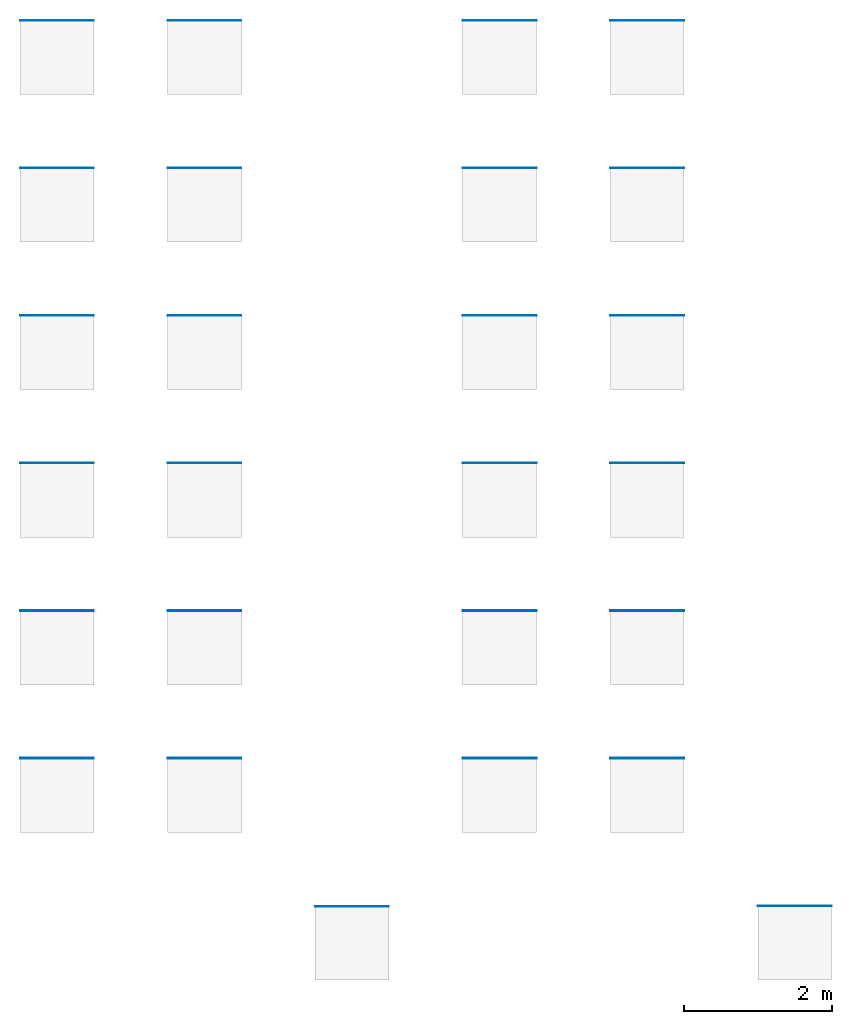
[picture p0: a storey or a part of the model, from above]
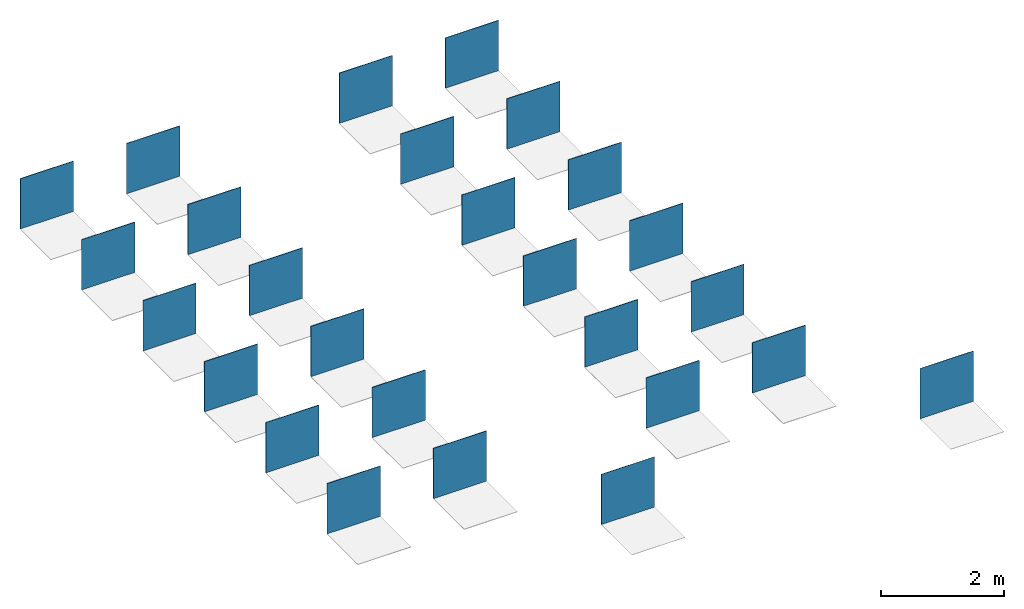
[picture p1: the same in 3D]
Properties of the parts of a building model (IFC2X3), part 1 of 4

# File
Description: ViewDefinition [CoordinationView_V2.0]
Time: 2025-06-20T15:38:36
Written by: The EXPRESS Data Manager Version 5.02.0100.07 : 28 Aug 2013
Made in: 21.1.90.15 - Exporter 21.1.90.15 - Alternate UI 21.1.90.15
Comment: STEP Physical File produced by: The EXPRESS Data Manager Version 5.02.0100.07 : 28 Aug 2013 * Module: EDMstepFileFactory/EDMstandAlone * Creation date: Fri Jun 20 15:38:36 2025 * Host: STB002 * Database: C:\Users\LARISS~1\AppData\Local\Temp\234e31d9-e186-458c-9206-d387dea7a233\cd15f4ba-808e-4852-9584-1646430fa52a\ifc * Database version: 5507 * Database creation date: Fri Jun 20 15:38:35 2025 * Schema: IFC2X3 * Model: DataRepository.ifc * Model creation date: Fri Jun 20 15:38:35 2025 * Header model: DataRepository.ifc_HeaderModel * Header model creation date: Fri Jun 20 15:38:35 2025 * EDMuser: sdai-user * EDMgroup: sdai-group * License ID and type: 5605 : Permanent license. Expiry date: * EDMstepFileFactory options: 020000

# IfcSite, Default
RefLatitude: 42, 24, 53, 508911; RefLongitude: -71, -15, -29, -58837; RefElevation: 0 mm
Pset_ProductRequirements - Category: Project Information

# IfcBuilding
Pset_BuildingCommon - NumberOfStoreys: 1
Pset_ProductRequirements - Category: Project Information

# IfcBuildingStorey: Level:Level 1, Level 1
LongName: Level 1; Elevation: 0 mm
Pset_AirSideSystemInformation - Name: Level 1
Pset_ProductRequirements - Name: Level 1; Category: Levels

# IfcCovering: Floor:REVIGRÉS-RULE-BASE-119,8x277,8-RECT-ALLOY, Floor:REVIGRÉS-RULE-BASE-119,8x277,8-RECT-ALLOY:18754
In: Level 1
Type - PredefinedType: FLOORING; Material: REVIGRÉS-RULE-BASE-119.8x277.8-RECT-ALLOY 6 mm
Type - Pset_CoveringCommon - Reference: 3021X4V711; Material: Grés porcelânico
Type - Pset_ElementShading - Roughness: 304.8 mm
Type - Pset_ManufacturerTypeInformation - Manufacturer: REVIGRÉS
Type - Pset_ProductRequirements - Category: Floors
Type - Pset_QuantityTakeOff - Reference: 3021X4V711
Type - IFC.REVIGRÉS-Dados do fabricante-Floor Covering - FabricanteURL: https://www.revigres.pt/; ReferenciaModelo: Rule; NumeroGlobalDeItemComercial: 3021X4V711; Acabamento: RECT; Material: Grés porcelânico; IdentificadorDoOperadorEconomico: 501840856; UrlFabricanteArtigo: https://www.revigres.pt/colecoes/omni; PaisOrigem: Portugal
Type - IFC.REVIGRÉS-Dados de desempenho-Floor Covering - LibertacaoDeCadmio: 0; LibertacaoDeChumbo: 0
Type - IFC.REVIGRÉS-Dados de especificação-Floor Covering - VariacaoTonalidade: 3; NivelDeTrafego: 5; EPavimento: Sim; ERevestimento: Sim; EExterno: Sim
Type - IFC.REVIGRÉS-Dados geométricos-Floor Covering - AlturaNominal: 6 mm; ComprimentoNominal: 119.8 mm; LarguraNominal: 277.8 mm
Type - IFC.REVIGRÉS-Dados de sustentabilidade-Floor Covering - ItemEParcialmenteReciclado: 0; EnergiaTermicaExportada: 0; ItemENovo: Sim; ItemEReciclado: Não; VidaÚtilEsperada: 50; SubstanciasPerigosas: Não; PotencialDeEsgotamentoAbioticoDosRecursosFosseis: 203; PotencialDeEsgotamentoAbioticoDosRecursosNaoFosseisMineraisEMetais: 0.000701; PotencialDeAquecimentoGlobalBiogenico: -0.48; CombustiveisFosseisComPotencialDeAquecimentoGlobal: 13.9; PotencialDeAquecimentoGlobalUsoDoSoloEMudancaDeUsoDoSolo: 0.0246; PotencialDeEutrofizacaoFraccaoDeNutrientesQueAtingemOCompartimentoFinalDeAguaDoce: 0.000189; PotencialDeEutrofizacaoFraccaoDeNutrientesQueAtingemOCompartimentoFinalMarinho: 0.0122; EnergiaRecuperada: 0.00739; ConsumoDeAguaDoce: 0.113; UtilizacaoLiquidaDeAguaDoce: 0.113; ResiduosPerigososEliminados: 0.00221; ResiduosNaoPerigososEliminados: 1.83; MassaTotalDeResiduosRadioactivosEliminados: 0.000394; EnergiaElectricaExportada: 1.55; MateriaisParaRecuperacaoDeEnergia: 0.00739; MateriaisParaReciclagem: 0.0253; UnidadeEPD: 1 m²
Type - IFC.REVIGRÉS-Dados gerais-Floor Covering - Nome: REVIGRÉS-RULE-BASE-119.8X277.8-RECT-ALLOY; TipoProduto: Prensado a seco: grupo BIa UGL | Grés porcelânico técnico; NumeroDeRegistoDAP: EPD-REV-20240006-CCC1-EN; ReferenciaDAP: -; UrlDOP: -
Classification: C3020 (Uniformat)
Pset_CoveringCommon - TotalThickness: 6 mm
IFC.REVIGRÉS-Dados do fabricante-Floor Covering - Type: Floor: REVIGRÉS-RULE-BASE-119,8x277,8-RECT-ALLOY
IFC.REVIGRÉS-Dados de desempenho-Floor Covering - Type: Floor: REVIGRÉS-RULE-BASE-119,8x277,8-RECT-ALLOY
IFC.REVIGRÉS-Dados de especificação-Floor Covering - Type: Floor: REVIGRÉS-RULE-BASE-119,8x277,8-RECT-ALLOY
IFC.REVIGRÉS-Dados geométricos-Floor Covering - Type: Floor: REVIGRÉS-RULE-BASE-119,8x277,8-RECT-ALLOY
IFC.REVIGRÉS-Dados de sustentabilidade-Floor Covering - Type: Floor: REVIGRÉS-RULE-BASE-119,8x277,8-RECT-ALLOY

# IfcCovering: Floor:REVIGRÉS-RULE-BASE-119,8x277,8-RECT-SMOG, Floor:REVIGRÉS-RULE-BASE-119,8x277,8-RECT-SMOG:17621
In: Level 1
Type - PredefinedType: FLOORING; Material: REVIGRÉS-RULE-BASE-119.8x277.8-RECT-SMOG 6 mm
Type - Pset_CoveringCommon - Reference: 3021X4V721; Material: Grés porcelânico
Type - Pset_ElementShading - Roughness: 304.8 mm
Type - Pset_ManufacturerTypeInformation - Manufacturer: REVIGRÉS
Type - Pset_ProductRequirements - Category: Floors
Type - Pset_QuantityTakeOff - Reference: 3021X4V721
Type - IFC.REVIGRÉS-Dados do fabricante-Floor Covering - FabricanteURL: https://www.revigres.pt/; ReferenciaModelo: Rule; NumeroGlobalDeItemComercial: 3021X4V721; Acabamento: RECT; Material: Grés porcelânico; IdentificadorDoOperadorEconomico: 501840856; UrlFabricanteArtigo: https://www.revigres.pt/colecoes/omni; PaisOrigem: Portugal
Type - IFC.REVIGRÉS-Dados de desempenho-Floor Covering - LibertacaoDeCadmio: 0; LibertacaoDeChumbo: 0
Type - IFC.REVIGRÉS-Dados de especificação-Floor Covering - VariacaoTonalidade: 3; NivelDeTrafego: 5; EPavimento: Sim; ERevestimento: Sim; EExterno: Sim
Type - IFC.REVIGRÉS-Dados geométricos-Floor Covering - AlturaNominal: 6 mm; ComprimentoNominal: 119.8 mm; LarguraNominal: 277.8 mm
Type - IFC.REVIGRÉS-Dados de sustentabilidade-Floor Covering - EnergiaTermicaExportada: 0; ItemENovo: Sim; ItemEParcialmenteReciclado: 0.23; ItemEReciclado: Sim; VidaÚtilEsperada: 50; SubstanciasPerigosas: Não; PotencialDeEsgotamentoAbioticoDosRecursosFosseis: 203; PotencialDeEsgotamentoAbioticoDosRecursosNaoFosseisMineraisEMetais: 0.000701; PotencialDeAquecimentoGlobalBiogenico: -0.48; CombustiveisFosseisComPotencialDeAquecimentoGlobal: 13.9; PotencialDeAquecimentoGlobalUsoDoSoloEMudancaDeUsoDoSolo: 0.0246; PotencialDeEutrofizacaoFraccaoDeNutrientesQueAtingemOCompartimentoFinalDeAguaDoce: 0.000189; PotencialDeEutrofizacaoFraccaoDeNutrientesQueAtingemOCompartimentoFinalMarinho: 0.0122; EnergiaRecuperada: 0.00739; ConsumoDeAguaDoce: 0.113; UtilizacaoLiquidaDeAguaDoce: 0.113; ResiduosPerigososEliminados: 0.00221; ResiduosNaoPerigososEliminados: 1.83; MassaTotalDeResiduosRadioactivosEliminados: 0.000394; EnergiaElectricaExportada: 1.55; MateriaisParaRecuperacaoDeEnergia: 0.00739; MateriaisParaReciclagem: 0.0253; UnidadeEPD: 1 m²
Type - IFC.REVIGRÉS-Dados gerais-Floor Covering - Nome: REVIGRÉS-RULE-BASE-119.8X277.8-RECT-SMOG; TipoProduto: Prensado a seco: grupo BIa UGL | Grés porcelânico técnico; NumeroDeRegistoDAP: EPD-REV-20240006-CCC1-EN; ReferenciaDAP: -; UrlDOP: -
Classification: C3020 (Uniformat)
Pset_CoveringCommon - TotalThickness: 6 mm
IFC.REVIGRÉS-Dados do fabricante-Floor Covering - Type: Floor: REVIGRÉS-RULE-BASE-119,8x277,8-RECT-SMOG
IFC.REVIGRÉS-Dados de desempenho-Floor Covering - Type: Floor: REVIGRÉS-RULE-BASE-119,8x277,8-RECT-SMOG
IFC.REVIGRÉS-Dados de especificação-Floor Covering - Type: Floor: REVIGRÉS-RULE-BASE-119,8x277,8-RECT-SMOG
IFC.REVIGRÉS-Dados geométricos-Floor Covering - Type: Floor: REVIGRÉS-RULE-BASE-119,8x277,8-RECT-SMOG
IFC.REVIGRÉS-Dados de sustentabilidade-Floor Covering - Type: Floor: REVIGRÉS-RULE-BASE-119,8x277,8-RECT-SMOG

# IfcCovering: Floor:REVIGRÉS-RULE-BASE-19,6x118,6-SILK-ALLOY, Floor:REVIGRÉS-RULE-BASE-19,6x118,6-SILK-ALLOY:2489
In: Level 1
Type - PredefinedType: FLOORING; Material: REVIGRÉS-RULE-BASE-19.6x118.6-SILK-ALLOY 10.5 mm
Type - Pset_CoveringCommon - Reference: 312GL8V711; Material: Grés porcelânico
Type - Pset_ElementShading - Roughness: 304.8 mm
Type - Pset_ManufacturerTypeInformation - Manufacturer: REVIGRÉS
Type - Pset_ProductRequirements - Category: Floors
Type - Pset_QuantityTakeOff - Reference: 312GL8V711
Type - IFC.REVIGRÉS-Dados do fabricante-Floor Covering - FabricanteURL: https://www.revigres.pt/; ReferenciaModelo: Rule; NumeroGlobalDeItemComercial: 312GL8V711; Acabamento: SILK; Material: Grés porcelânico; IdentificadorDoOperadorEconomico: 501840856; UrlFabricanteArtigo: https://www.revigres.pt/colecoes/rule; PaisOrigem: Portugal
Type - IFC.REVIGRÉS-Dados de desempenho-Floor Covering - Rectilinearidade: ± 0.2% máx.± 0.8 mm; Ortogonalidade: ± 0.2% máx.± 1.5 mm; PlanaridadeDaSuperficie: ± 0.3% máx. ± 1.8 mm; QualidadeDaSuperficie: Cumpre; AbsorcaoDeAgua: < 0.05%; ModuloDeRuptura: > 45 N/mm²; ResistenciaAFlexao: >3500 N; ResistenciaAAbrasaoProfunda: < 120 mm³; DilatacaoTermicaLinear: ≤ 8,0x10-6 °C-1; ResistenciaAoChoqueTermico: Resiste; DurabilidadeResistenciaAoGeloDegelo: Resiste; ResistenciaAoEscorregamentoDIN51130: R9; ResistenciaAoEscorregamentoDIN51097: A; ResistenciaAoEscorregamentoENV51097: A; ResistenciaAoEscorregamentoENV12633: Class 1; ResistenciaAoEscorregamentoANSIA1371: ≥0,42; ResistenciaAoDeslizamentoENV12633: Class 1; ResistenciaAsManchas: Class 5; ResistenciaABaixasConcentracoesDeAcidosEAlcalis: Classe LA; ResistenciaAAltasConcentracoesDeAcidosEAlcalis: Classe HA; LibertacaoDeCadmio: 0; LibertacaoDeChumbo: 0
Type - IFC.REVIGRÉS-Dados de especificação-Floor Covering - VariacaoTonalidade: 3; NivelDeTrafego: 5; EPavimento: Sim; ERevestimento: Sim; EExterno: Sim
Type - IFC.REVIGRÉS-Dados geométricos-Floor Covering - AlturaNominal: 10.5 mm; ComprimentoNominal: 19.6 mm; LarguraNominal: 118.6 mm
Type - IFC.REVIGRÉS-Dados de sustentabilidade-Floor Covering - ItemEParcialmenteReciclado: 0; EnergiaTermicaExportada: 0; ItemENovo: Sim; ItemEReciclado: Não; VidaÚtilEsperada: 50; SubstanciasPerigosas: Não; PotencialDeEsgotamentoAbioticoDosRecursosFosseis: 203; PotencialDeEsgotamentoAbioticoDosRecursosNaoFosseisMineraisEMetais: 0.000701; PotencialDeAquecimentoGlobalBiogenico: -0.48; CombustiveisFosseisComPotencialDeAquecimentoGlobal: 13.9; PotencialDeAquecimentoGlobalUsoDoSoloEMudancaDeUsoDoSolo: 0.0246; PotencialDeEutrofizacaoFraccaoDeNutrientesQueAtingemOCompartimentoFinalDeAguaDoce: 0.000189; PotencialDeEutrofizacaoFraccaoDeNutrientesQueAtingemOCompartimentoFinalMarinho: 0.0122; EnergiaRecuperada: 0.00739; ConsumoDeAguaDoce: 0.113; UtilizacaoLiquidaDeAguaDoce: 0.113; ResiduosPerigososEliminados: 0.00221; ResiduosNaoPerigososEliminados: 1.83; MassaTotalDeResiduosRadioactivosEliminados: 0.000394; EnergiaElectricaExportada: 1.55; MateriaisParaRecuperacaoDeEnergia: 0.00739; MateriaisParaReciclagem: 0.0253; UnidadeEPD: 1 m²
Type - IFC.REVIGRÉS-Dados gerais-Floor Covering - Nome: REVIGRÉS-RULE-BASE-19.6X118.6-SILK-ALLOY; TipoProduto: Prensado a seco: grupo BIa UGL | Grés porcelânico técnico; NumeroDeRegistoDAP: EPD-REV-20240006-CCC1-EN; ReferenciaDAP: -; UrlDOP: -
Classification: C3020 (Uniformat)
Pset_CoveringCommon - TotalThickness: 10.5 mm
IFC.REVIGRÉS-Dados do fabricante-Floor Covering - Type: Floor: REVIGRÉS-RULE-BASE-19,6x118,6-SILK-ALLOY
IFC.REVIGRÉS-Dados de desempenho-Floor Covering - Type: Floor: REVIGRÉS-RULE-BASE-19,6x118,6-SILK-ALLOY
IFC.REVIGRÉS-Dados de especificação-Floor Covering - Type: Floor: REVIGRÉS-RULE-BASE-19,6x118,6-SILK-ALLOY
IFC.REVIGRÉS-Dados geométricos-Floor Covering - Type: Floor: REVIGRÉS-RULE-BASE-19,6x118,6-SILK-ALLOY
IFC.REVIGRÉS-Dados de sustentabilidade-Floor Covering - Type: Floor: REVIGRÉS-RULE-BASE-19,6x118,6-SILK-ALLOY

# IfcCovering: Floor:REVIGRÉS-RULE-BASE-19,6x118,6-SILK-SMOG, Floor:REVIGRÉS-RULE-BASE-19,6x118,6-SILK-SMOG:10931
In: Level 1
Type - PredefinedType: FLOORING; Material: REVIGRÉS-RULE-BASE-19.6x118.6-SILK-SMOG 10.5 mm
Type - Pset_CoveringCommon - Reference: 312GL8V721; Material: Grés porcelânico
Type - Pset_ElementShading - Roughness: 304.8 mm
Type - Pset_ManufacturerTypeInformation - Manufacturer: REVIGRÉS
Type - Pset_ProductRequirements - Category: Floors
Type - Pset_QuantityTakeOff - Reference: 312GL8V721
Type - IFC.REVIGRÉS-Dados do fabricante-Floor Covering - FabricanteURL: https://www.revigres.pt/; ReferenciaModelo: Rule; NumeroGlobalDeItemComercial: 312GL8V721; Acabamento: SILK; Material: Grés porcelânico; IdentificadorDoOperadorEconomico: 501840856; UrlFabricanteArtigo: https://www.revigres.pt/colecoes/rule; PaisOrigem: Portugal
Type - IFC.REVIGRÉS-Dados de desempenho-Floor Covering - Rectilinearidade: ± 0.2% máx.± 0.8 mm; Ortogonalidade: ± 0.2% máx.± 1.5 mm; PlanaridadeDaSuperficie: ± 0.3% máx. ± 1.8 mm; QualidadeDaSuperficie: Cumpre; AbsorcaoDeAgua: < 0.05%; ModuloDeRuptura: > 45 N/mm²; ResistenciaAFlexao: >3500 N; ResistenciaAAbrasaoProfunda: < 120 mm³; DilatacaoTermicaLinear: ≤ 8,0x10-6 °C-1; ResistenciaAoChoqueTermico: Resiste; DurabilidadeResistenciaAoGeloDegelo: Resiste; ResistenciaAoEscorregamentoDIN51130: R9; ResistenciaAoEscorregamentoDIN51097: A; ResistenciaAoEscorregamentoENV51097: A; ResistenciaAoEscorregamentoENV12633: Class 1; ResistenciaAoEscorregamentoANSIA1371: ≥0,42; ResistenciaAoDeslizamentoENV12633: Class 1; ResistenciaAsManchas: Class 5; ResistenciaABaixasConcentracoesDeAcidosEAlcalis: Classe LA; ResistenciaAAltasConcentracoesDeAcidosEAlcalis: Classe HA; LibertacaoDeCadmio: 0; LibertacaoDeChumbo: 0
Type - IFC.REVIGRÉS-Dados de especificação-Floor Covering - VariacaoTonalidade: 3; NivelDeTrafego: 5; EPavimento: Sim; ERevestimento: Sim; EExterno: Sim
Type - IFC.REVIGRÉS-Dados geométricos-Floor Covering - AlturaNominal: 10.5 mm; ComprimentoNominal: 19.6 mm; LarguraNominal: 118.6 mm
Type - IFC.REVIGRÉS-Dados de sustentabilidade-Floor Covering - EnergiaTermicaExportada: 0; ItemENovo: Sim; ItemEParcialmenteReciclado: 0.23; ItemEReciclado: Sim; VidaÚtilEsperada: 50; SubstanciasPerigosas: Não; PotencialDeEsgotamentoAbioticoDosRecursosFosseis: 203; PotencialDeEsgotamentoAbioticoDosRecursosNaoFosseisMineraisEMetais: 0.000701; PotencialDeAquecimentoGlobalBiogenico: -0.48; CombustiveisFosseisComPotencialDeAquecimentoGlobal: 13.9; PotencialDeAquecimentoGlobalUsoDoSoloEMudancaDeUsoDoSolo: 0.0246; PotencialDeEutrofizacaoFraccaoDeNutrientesQueAtingemOCompartimentoFinalDeAguaDoce: 0.000189; PotencialDeEutrofizacaoFraccaoDeNutrientesQueAtingemOCompartimentoFinalMarinho: 0.0122; EnergiaRecuperada: 0.00739; ConsumoDeAguaDoce: 0.113; UtilizacaoLiquidaDeAguaDoce: 0.113; ResiduosPerigososEliminados: 0.00221; ResiduosNaoPerigososEliminados: 1.83; MassaTotalDeResiduosRadioactivosEliminados: 0.000394; EnergiaElectricaExportada: 1.55; MateriaisParaRecuperacaoDeEnergia: 0.00739; MateriaisParaReciclagem: 0.0253; UnidadeEPD: 1 m²
Type - IFC.REVIGRÉS-Dados gerais-Floor Covering - Nome: REVIGRÉS-RULE-BASE-19.6X118.6-SILK-SMOG; TipoProduto: Prensado a seco: grupo BIa UGL | Grés porcelânico técnico; NumeroDeRegistoDAP: EPD-REV-20240006-CCC1-EN; ReferenciaDAP: -; UrlDOP: -
Classification: C3020 (Uniformat)
Pset_CoveringCommon - TotalThickness: 10.5 mm
IFC.REVIGRÉS-Dados do fabricante-Floor Covering - Type: Floor: REVIGRÉS-RULE-BASE-19,6x118,6-SILK-SMOG
IFC.REVIGRÉS-Dados de desempenho-Floor Covering - Type: Floor: REVIGRÉS-RULE-BASE-19,6x118,6-SILK-SMOG
IFC.REVIGRÉS-Dados de especificação-Floor Covering - Type: Floor: REVIGRÉS-RULE-BASE-19,6x118,6-SILK-SMOG
IFC.REVIGRÉS-Dados geométricos-Floor Covering - Type: Floor: REVIGRÉS-RULE-BASE-19,6x118,6-SILK-SMOG
IFC.REVIGRÉS-Dados de sustentabilidade-Floor Covering - Type: Floor: REVIGRÉS-RULE-BASE-19,6x118,6-SILK-SMOG

# IfcCovering: Floor:REVIGRÉS-RULE-BASE-19,6x118,6-SOFT GRIP-ALLOY, Floor:REVIGRÉS-RULE-BASE-19,6x118,6-SOFT GRIP-ALLOY:11150
In: Level 1
Type - PredefinedType: FLOORING; Material: REVIGRÉS-RULE-BASE-19.6x118.6-SOFT GRIP-ALLOY 10.5 mm
Type - Pset_CoveringCommon - Reference: 3121L8V711; Material: Grés porcelânico
Type - Pset_ElementShading - Roughness: 304.8 mm
Type - Pset_ManufacturerTypeInformation - Manufacturer: REVIGRÉS
Type - Pset_ProductRequirements - Category: Floors
Type - Pset_QuantityTakeOff - Reference: 3121L8V711
Type - IFC.REVIGRÉS-Dados do fabricante-Floor Covering - FabricanteURL: https://www.revigres.pt/; ReferenciaModelo: Rule; NumeroGlobalDeItemComercial: 3121L8V711; Acabamento: SOFT GRIP; Material: Grés porcelânico; IdentificadorDoOperadorEconomico: 501840856; UrlFabricanteArtigo: https://www.revigres.pt/colecoes/rule; PaisOrigem: Portugal
Type - IFC.REVIGRÉS-Dados de desempenho-Floor Covering - Rectilinearidade: ± 0.2% máx.± 0.8 mm; Ortogonalidade: ± 0.2% máx.± 1.5 mm; PlanaridadeDaSuperficie: ± 0.3% máx. ± 1.8 mm; QualidadeDaSuperficie: Cumpre; AbsorcaoDeAgua: < 0.05%; ModuloDeRuptura: > 45 N/mm²; ResistenciaAFlexao: >3500 N; ResistenciaAAbrasaoProfunda: < 120 mm³; DilatacaoTermicaLinear: ≤ 8,0x10-6 °C-1; ResistenciaAoChoqueTermico: Resiste; DurabilidadeResistenciaAoGeloDegelo: Resiste; ResistenciaAoEscorregamentoDIN51130: R11; ResistenciaAoEscorregamentoDIN51097: B; ResistenciaAoEscorregamentoENV51097: B; ResistenciaAoEscorregamentoENV12633: Class 2; ResistenciaAoEscorregamentoBS7976: >36; ResistenciaAoEscorregamentoANSIA1371: ≥0,42; ResistenciaAoDeslizamentoENV12633: Class 2; ResistenciaAoDeslizamentoBS7976: >36; ResistenciaAsManchas: Class 5; ResistenciaABaixasConcentracoesDeAcidosEAlcalis: Classe LA; ResistenciaAAltasConcentracoesDeAcidosEAlcalis: Classe HA; LibertacaoDeCadmio: 0; LibertacaoDeChumbo: 0
Type - IFC.REVIGRÉS-Dados de especificação-Floor Covering - VariacaoTonalidade: 3; NivelDeTrafego: 5; EPavimento: Sim; ERevestimento: Sim; EExterno: Sim
Type - IFC.REVIGRÉS-Dados geométricos-Floor Covering - AlturaNominal: 10.5 mm; ComprimentoNominal: 19.6 mm; LarguraNominal: 118.6 mm
Type - IFC.REVIGRÉS-Dados de sustentabilidade-Floor Covering - ItemEParcialmenteReciclado: 0; EnergiaTermicaExportada: 0; ItemENovo: Sim; ItemEReciclado: Não; VidaÚtilEsperada: 50; SubstanciasPerigosas: Não; PotencialDeEsgotamentoAbioticoDosRecursosFosseis: 203; PotencialDeEsgotamentoAbioticoDosRecursosNaoFosseisMineraisEMetais: 0.000701; PotencialDeAquecimentoGlobalBiogenico: -0.48; CombustiveisFosseisComPotencialDeAquecimentoGlobal: 13.9; PotencialDeAquecimentoGlobalUsoDoSoloEMudancaDeUsoDoSolo: 0.0246; PotencialDeEutrofizacaoFraccaoDeNutrientesQueAtingemOCompartimentoFinalDeAguaDoce: 0.000189; PotencialDeEutrofizacaoFraccaoDeNutrientesQueAtingemOCompartimentoFinalMarinho: 0.0122; EnergiaRecuperada: 0.00739; ConsumoDeAguaDoce: 0.113; UtilizacaoLiquidaDeAguaDoce: 0.113; ResiduosPerigososEliminados: 0.00221; ResiduosNaoPerigososEliminados: 1.83; MassaTotalDeResiduosRadioactivosEliminados: 0.000394; EnergiaElectricaExportada: 1.55; MateriaisParaRecuperacaoDeEnergia: 0.00739; MateriaisParaReciclagem: 0.0253; UnidadeEPD: 1 m²
Type - IFC.REVIGRÉS-Dados gerais-Floor Covering - Nome: REVIGRÉS-RULE-BASE-19.6X118.6-SOFT GRIP-ALLOY; TipoProduto: Prensado a seco: grupo BIa UGL | Grés porcelânico técnico; NumeroDeRegistoDAP: EPD-REV-20240006-CCC1-EN; ReferenciaDAP: -; UrlDOP: -
Classification: C3020 (Uniformat)
Pset_CoveringCommon - TotalThickness: 10.5 mm
IFC.REVIGRÉS-Dados do fabricante-Floor Covering - Type: Floor: REVIGRÉS-RULE-BASE-19,6x118,6-SOFT GRIP-ALLOY
IFC.REVIGRÉS-Dados de desempenho-Floor Covering - Type: Floor: REVIGRÉS-RULE-BASE-19,6x118,6-SOFT GRIP-ALLOY
IFC.REVIGRÉS-Dados de especificação-Floor Covering - Type: Floor: REVIGRÉS-RULE-BASE-19,6x118,6-SOFT GRIP-ALLOY
IFC.REVIGRÉS-Dados geométricos-Floor Covering - Type: Floor: REVIGRÉS-RULE-BASE-19,6x118,6-SOFT GRIP-ALLOY
IFC.REVIGRÉS-Dados de sustentabilidade-Floor Covering - Type: Floor: REVIGRÉS-RULE-BASE-19,6x118,6-SOFT GRIP-ALLOY

# IfcCovering: Floor:REVIGRÉS-RULE-BASE-19,6x118,6-SOFT GRIP-SMOG, Floor:REVIGRÉS-RULE-BASE-19,6x118,6-SOFT GRIP-SMOG:11228
In: Level 1
Type - PredefinedType: FLOORING; Material: REVIGRÉS-RULE-BASE-19.6x118.6-SOFT GRIP-SMOG 10.5 mm
Type - Pset_CoveringCommon - Reference: 312FL8V721; Material: Grés porcelânico
Type - Pset_ElementShading - Roughness: 304.8 mm
Type - Pset_ManufacturerTypeInformation - Manufacturer: REVIGRÉS
Type - Pset_ProductRequirements - Category: Floors
Type - Pset_QuantityTakeOff - Reference: 312FL8V721
Type - IFC.REVIGRÉS-Dados do fabricante-Floor Covering - FabricanteURL: https://www.revigres.pt/; ReferenciaModelo: Rule; NumeroGlobalDeItemComercial: 312FL8V721; Acabamento: SOFT GRIP; Material: Grés porcelânico; IdentificadorDoOperadorEconomico: 501840856; UrlFabricanteArtigo: https://www.revigres.pt/colecoes/rule; PaisOrigem: Portugal
Type - IFC.REVIGRÉS-Dados de desempenho-Floor Covering - Rectilinearidade: ± 0.2% máx.± 0.8 mm; Ortogonalidade: ± 0.2% máx.± 1.5 mm; PlanaridadeDaSuperficie: ± 0.3% máx. ± 1.8 mm; QualidadeDaSuperficie: Cumpre; AbsorcaoDeAgua: < 0.05%; ModuloDeRuptura: > 45 N/mm²; ResistenciaAFlexao: >3500 N; ResistenciaAAbrasaoProfunda: < 120 mm³; DilatacaoTermicaLinear: ≤ 8,0x10-6 °C-1; ResistenciaAoChoqueTermico: Resiste; DurabilidadeResistenciaAoGeloDegelo: Resiste; ResistenciaAoEscorregamentoDIN51130: R11; ResistenciaAoEscorregamentoDIN51097: B; ResistenciaAoEscorregamentoENV51097: B; ResistenciaAoEscorregamentoENV12633: Class 2; ResistenciaAoEscorregamentoBS7976: >36; ResistenciaAoEscorregamentoANSIA1371: ≥0,42; ResistenciaAoDeslizamentoENV12633: Class 2; ResistenciaAoDeslizamentoBS7976: >36; ResistenciaAsManchas: Class 5; ResistenciaABaixasConcentracoesDeAcidosEAlcalis: Classe LA; ResistenciaAAltasConcentracoesDeAcidosEAlcalis: Classe HA; LibertacaoDeCadmio: 0; LibertacaoDeChumbo: 0
Type - IFC.REVIGRÉS-Dados de especificação-Floor Covering - VariacaoTonalidade: 3; NivelDeTrafego: 5; EPavimento: Sim; ERevestimento: Sim; EExterno: Sim
Type - IFC.REVIGRÉS-Dados geométricos-Floor Covering - AlturaNominal: 10.5 mm; ComprimentoNominal: 19.6 mm; LarguraNominal: 118.6 mm
Type - IFC.REVIGRÉS-Dados de sustentabilidade-Floor Covering - EnergiaTermicaExportada: 0; ItemENovo: Sim; ItemEParcialmenteReciclado: 0.23; ItemEReciclado: Sim; VidaÚtilEsperada: 50; SubstanciasPerigosas: Não; PotencialDeEsgotamentoAbioticoDosRecursosFosseis: 203; PotencialDeEsgotamentoAbioticoDosRecursosNaoFosseisMineraisEMetais: 0.000701; PotencialDeAquecimentoGlobalBiogenico: -0.48; CombustiveisFosseisComPotencialDeAquecimentoGlobal: 13.9; PotencialDeAquecimentoGlobalUsoDoSoloEMudancaDeUsoDoSolo: 0.0246; PotencialDeEutrofizacaoFraccaoDeNutrientesQueAtingemOCompartimentoFinalDeAguaDoce: 0.000189; PotencialDeEutrofizacaoFraccaoDeNutrientesQueAtingemOCompartimentoFinalMarinho: 0.0122; EnergiaRecuperada: 0.00739; ConsumoDeAguaDoce: 0.113; UtilizacaoLiquidaDeAguaDoce: 0.113; ResiduosPerigososEliminados: 0.00221; ResiduosNaoPerigososEliminados: 1.83; MassaTotalDeResiduosRadioactivosEliminados: 0.000394; EnergiaElectricaExportada: 1.55; MateriaisParaRecuperacaoDeEnergia: 0.00739; MateriaisParaReciclagem: 0.0253; UnidadeEPD: 1 m²
Type - IFC.REVIGRÉS-Dados gerais-Floor Covering - Nome: REVIGRÉS-RULE-BASE-19.6X118.6-SOFT GRIP-SMOG; TipoProduto: Prensado a seco: grupo BIa UGL | Grés porcelânico técnico; NumeroDeRegistoDAP: EPD-REV-20240006-CCC1-EN; ReferenciaDAP: -; UrlDOP: -
Classification: C3020 (Uniformat)
Pset_CoveringCommon - TotalThickness: 10.5 mm
IFC.REVIGRÉS-Dados do fabricante-Floor Covering - Type: Floor: REVIGRÉS-RULE-BASE-19,6x118,6-SOFT GRIP-SMOG
IFC.REVIGRÉS-Dados de desempenho-Floor Covering - Type: Floor: REVIGRÉS-RULE-BASE-19,6x118,6-SOFT GRIP-SMOG
IFC.REVIGRÉS-Dados de especificação-Floor Covering - Type: Floor: REVIGRÉS-RULE-BASE-19,6x118,6-SOFT GRIP-SMOG
IFC.REVIGRÉS-Dados geométricos-Floor Covering - Type: Floor: REVIGRÉS-RULE-BASE-19,6x118,6-SOFT GRIP-SMOG
IFC.REVIGRÉS-Dados de sustentabilidade-Floor Covering - Type: Floor: REVIGRÉS-RULE-BASE-19,6x118,6-SOFT GRIP-SMOG

# IfcCovering: Floor:REVIGRÉS-RULE-BASE-19,6x178-SILK-ALLOY, Floor:REVIGRÉS-RULE-BASE-19,6x178-SILK-ALLOY:11306
In: Level 1
Type - PredefinedType: FLOORING; Material: REVIGRÉS-RULE-BASE-19.6x178-SILK-ALLOY 11.2 mm
Type - Pset_CoveringCommon - Reference: 312GS8V711; Material: Grés porcelânico
Type - Pset_ElementShading - Roughness: 304.8 mm
Type - Pset_ManufacturerTypeInformation - Manufacturer: REVIGRÉS
Type - Pset_ProductRequirements - Category: Floors
Type - Pset_QuantityTakeOff - Reference: 312GS8V711
Type - IFC.REVIGRÉS-Dados do fabricante-Floor Covering - FabricanteURL: https://www.revigres.pt/; ReferenciaModelo: Rule; NumeroGlobalDeItemComercial: 312GS8V711; Acabamento: SILK; Material: Grés porcelânico; IdentificadorDoOperadorEconomico: 501840856; UrlFabricanteArtigo: https://www.revigres.pt/colecoes/rule; PaisOrigem: Portugal
Type - IFC.REVIGRÉS-Dados de desempenho-Floor Covering - Rectilinearidade: ± 0.2% máx.± 0.8 mm; Ortogonalidade: ± 0.2% máx.± 1.5 mm; PlanaridadeDaSuperficie: ± 0.3% máx. ± 1.8 mm; QualidadeDaSuperficie: Cumpre; AbsorcaoDeAgua: < 0.05%; ModuloDeRuptura: > 45 N/mm²; ResistenciaAFlexao: >3500 N; ResistenciaAAbrasaoProfunda: < 120 mm³; DilatacaoTermicaLinear: ≤ 8,0x10-6 °C-1; ResistenciaAoChoqueTermico: Resiste; DurabilidadeResistenciaAoGeloDegelo: Resiste; ResistenciaAoEscorregamentoDIN51130: R9; ResistenciaAoEscorregamentoDIN51097: A; ResistenciaAoEscorregamentoENV51097: A; ResistenciaAoEscorregamentoENV12633: Class 1; ResistenciaAoEscorregamentoANSIA1371: ≥0,42; ResistenciaAoDeslizamentoENV12633: Class 1; ResistenciaAsManchas: Class 5; ResistenciaABaixasConcentracoesDeAcidosEAlcalis: Classe LA; ResistenciaAAltasConcentracoesDeAcidosEAlcalis: Classe HA; LibertacaoDeCadmio: 0; LibertacaoDeChumbo: 0
Type - IFC.REVIGRÉS-Dados de especificação-Floor Covering - VariacaoTonalidade: 3; NivelDeTrafego: 5; EPavimento: Sim; ERevestimento: Sim; EExterno: Sim
Type - IFC.REVIGRÉS-Dados geométricos-Floor Covering - AlturaNominal: 11.2 mm; ComprimentoNominal: 19.6 mm; LarguraNominal: 178 mm
Type - IFC.REVIGRÉS-Dados de sustentabilidade-Floor Covering - ItemEParcialmenteReciclado: 0; EnergiaTermicaExportada: 0; ItemENovo: Sim; ItemEReciclado: Não; VidaÚtilEsperada: 50; SubstanciasPerigosas: Não; PotencialDeEsgotamentoAbioticoDosRecursosFosseis: 203; PotencialDeEsgotamentoAbioticoDosRecursosNaoFosseisMineraisEMetais: 0.000701; PotencialDeAquecimentoGlobalBiogenico: -0.48; CombustiveisFosseisComPotencialDeAquecimentoGlobal: 13.9; PotencialDeAquecimentoGlobalUsoDoSoloEMudancaDeUsoDoSolo: 0.0246; PotencialDeEutrofizacaoFraccaoDeNutrientesQueAtingemOCompartimentoFinalDeAguaDoce: 0.000189; PotencialDeEutrofizacaoFraccaoDeNutrientesQueAtingemOCompartimentoFinalMarinho: 0.0122; EnergiaRecuperada: 0.00739; ConsumoDeAguaDoce: 0.113; UtilizacaoLiquidaDeAguaDoce: 0.113; ResiduosPerigososEliminados: 0.00221; ResiduosNaoPerigososEliminados: 1.83; MassaTotalDeResiduosRadioactivosEliminados: 0.000394; EnergiaElectricaExportada: 1.55; MateriaisParaRecuperacaoDeEnergia: 0.00739; MateriaisParaReciclagem: 0.0253; UnidadeEPD: 1 m²
Type - IFC.REVIGRÉS-Dados gerais-Floor Covering - Nome: REVIGRÉS-RULE-BASE-19.6X178-SILK-ALLOY; TipoProduto: Prensado a seco: grupo BIa UGL | Grés porcelânico técnico; NumeroDeRegistoDAP: EPD-REV-20240006-CCC1-EN; ReferenciaDAP: -; UrlDOP: -
Classification: C3020 (Uniformat)
Pset_CoveringCommon - TotalThickness: 11.2 mm
IFC.REVIGRÉS-Dados do fabricante-Floor Covering - Type: Floor: REVIGRÉS-RULE-BASE-19,6x178-SILK-ALLOY
IFC.REVIGRÉS-Dados de desempenho-Floor Covering - Type: Floor: REVIGRÉS-RULE-BASE-19,6x178-SILK-ALLOY
IFC.REVIGRÉS-Dados de especificação-Floor Covering - Type: Floor: REVIGRÉS-RULE-BASE-19,6x178-SILK-ALLOY
IFC.REVIGRÉS-Dados geométricos-Floor Covering - Type: Floor: REVIGRÉS-RULE-BASE-19,6x178-SILK-ALLOY
IFC.REVIGRÉS-Dados de sustentabilidade-Floor Covering - Type: Floor: REVIGRÉS-RULE-BASE-19,6x178-SILK-ALLOY

# IfcCovering: Floor:REVIGRÉS-RULE-BASE-19,6x178-SILK-SMOG, Floor:REVIGRÉS-RULE-BASE-19,6x178-SILK-SMOG:11369
In: Level 1
Type - PredefinedType: FLOORING; Material: REVIGRÉS-RULE-BASE-19.6x178-SILK-SMOG 11.2 mm
Type - Pset_CoveringCommon - Reference: 312GS8V721; Material: Grés porcelânico
Type - Pset_ElementShading - Roughness: 304.8 mm
Type - Pset_ManufacturerTypeInformation - Manufacturer: REVIGRÉS
Type - Pset_ProductRequirements - Category: Floors
Type - Pset_QuantityTakeOff - Reference: 312GS8V721
Type - IFC.REVIGRÉS-Dados do fabricante-Floor Covering - FabricanteURL: https://www.revigres.pt/; ReferenciaModelo: Rule; NumeroGlobalDeItemComercial: 312GS8V721; Acabamento: SILK; Material: Grés porcelânico; IdentificadorDoOperadorEconomico: 501840856; UrlFabricanteArtigo: https://www.revigres.pt/colecoes/rule; PaisOrigem: Portugal
Type - IFC.REVIGRÉS-Dados de desempenho-Floor Covering - Rectilinearidade: ± 0.2% máx.± 0.8 mm; Ortogonalidade: ± 0.2% máx.± 1.5 mm; PlanaridadeDaSuperficie: ± 0.3% máx. ± 1.8 mm; QualidadeDaSuperficie: Cumpre; AbsorcaoDeAgua: < 0.05%; ModuloDeRuptura: > 45 N/mm²; ResistenciaAFlexao: >3500 N; ResistenciaAAbrasaoProfunda: < 120 mm³; DilatacaoTermicaLinear: ≤ 8,0x10-6 °C-1; ResistenciaAoChoqueTermico: Resiste; DurabilidadeResistenciaAoGeloDegelo: Resiste; ResistenciaAoEscorregamentoDIN51130: R9; ResistenciaAoEscorregamentoDIN51097: A; ResistenciaAoEscorregamentoENV51097: A; ResistenciaAoEscorregamentoENV12633: Class 1; ResistenciaAoEscorregamentoANSIA1371: ≥0,42; ResistenciaAoDeslizamentoENV12633: Class 1; ResistenciaAsManchas: Class 5; ResistenciaABaixasConcentracoesDeAcidosEAlcalis: Classe LA; ResistenciaAAltasConcentracoesDeAcidosEAlcalis: Classe HA; LibertacaoDeCadmio: 0; LibertacaoDeChumbo: 0
Type - IFC.REVIGRÉS-Dados de especificação-Floor Covering - VariacaoTonalidade: 3; NivelDeTrafego: 5; EPavimento: Sim; ERevestimento: Sim; EExterno: Sim
Type - IFC.REVIGRÉS-Dados geométricos-Floor Covering - AlturaNominal: 11.2 mm; ComprimentoNominal: 19.6 mm; LarguraNominal: 178 mm
Type - IFC.REVIGRÉS-Dados de sustentabilidade-Floor Covering - EnergiaTermicaExportada: 0; ItemENovo: Sim; ItemEParcialmenteReciclado: 0.23; ItemEReciclado: Sim; VidaÚtilEsperada: 50; SubstanciasPerigosas: Não; PotencialDeEsgotamentoAbioticoDosRecursosFosseis: 203; PotencialDeEsgotamentoAbioticoDosRecursosNaoFosseisMineraisEMetais: 0.000701; PotencialDeAquecimentoGlobalBiogenico: -0.48; CombustiveisFosseisComPotencialDeAquecimentoGlobal: 13.9; PotencialDeAquecimentoGlobalUsoDoSoloEMudancaDeUsoDoSolo: 0.0246; PotencialDeEutrofizacaoFraccaoDeNutrientesQueAtingemOCompartimentoFinalDeAguaDoce: 0.000189; PotencialDeEutrofizacaoFraccaoDeNutrientesQueAtingemOCompartimentoFinalMarinho: 0.0122; EnergiaRecuperada: 0.00739; ConsumoDeAguaDoce: 0.113; UtilizacaoLiquidaDeAguaDoce: 0.113; ResiduosPerigososEliminados: 0.00221; ResiduosNaoPerigososEliminados: 1.83; MassaTotalDeResiduosRadioactivosEliminados: 0.000394; EnergiaElectricaExportada: 1.55; MateriaisParaRecuperacaoDeEnergia: 0.00739; MateriaisParaReciclagem: 0.0253; UnidadeEPD: 1 m²
Type - IFC.REVIGRÉS-Dados gerais-Floor Covering - Nome: REVIGRÉS-RULE-BASE-19.6X178-SILK-SMOG; TipoProduto: Prensado a seco: grupo BIa UGL | Grés porcelânico técnico; NumeroDeRegistoDAP: EPD-REV-20240006-CCC1-EN; ReferenciaDAP: -; UrlDOP: -
Classification: C3020 (Uniformat)
Pset_CoveringCommon - TotalThickness: 11.2 mm
IFC.REVIGRÉS-Dados do fabricante-Floor Covering - Type: Floor: REVIGRÉS-RULE-BASE-19,6x178-SILK-SMOG
IFC.REVIGRÉS-Dados de desempenho-Floor Covering - Type: Floor: REVIGRÉS-RULE-BASE-19,6x178-SILK-SMOG
IFC.REVIGRÉS-Dados de especificação-Floor Covering - Type: Floor: REVIGRÉS-RULE-BASE-19,6x178-SILK-SMOG
IFC.REVIGRÉS-Dados geométricos-Floor Covering - Type: Floor: REVIGRÉS-RULE-BASE-19,6x178-SILK-SMOG
IFC.REVIGRÉS-Dados de sustentabilidade-Floor Covering - Type: Floor: REVIGRÉS-RULE-BASE-19,6x178-SILK-SMOG

# IfcCovering: Floor:REVIGRÉS-RULE-BASE-19,6x178-SOFT GRIP-ALLOY, Floor:REVIGRÉS-RULE-BASE-19,6x178-SOFT GRIP-ALLOY:11431
In: Level 1
Type - PredefinedType: FLOORING; Material: REVIGRÉS-RULE-BASE-19.6x178-SOFT GRIP-ALLOY 11.2 mm
Type - Pset_CoveringCommon - Reference: 312FS8V711; Material: Grés porcelânico
Type - Pset_ElementShading - Roughness: 304.8 mm
Type - Pset_ManufacturerTypeInformation - Manufacturer: REVIGRÉS
Type - Pset_ProductRequirements - Category: Floors
Type - Pset_QuantityTakeOff - Reference: 312FS8V711
Type - IFC.REVIGRÉS-Dados do fabricante-Floor Covering - FabricanteURL: https://www.revigres.pt/; ReferenciaModelo: Rule; NumeroGlobalDeItemComercial: 312FS8V711; Acabamento: SOFT GRIP; Material: Grés porcelânico; IdentificadorDoOperadorEconomico: 501840856; UrlFabricanteArtigo: https://www.revigres.pt/colecoes/rule; PaisOrigem: Portugal
Type - IFC.REVIGRÉS-Dados de desempenho-Floor Covering - Rectilinearidade: ± 0.2% máx.± 0.8 mm; Ortogonalidade: ± 0.2% máx.± 1.5 mm; PlanaridadeDaSuperficie: ± 0.3% máx. ± 1.8 mm; QualidadeDaSuperficie: Cumpre; AbsorcaoDeAgua: < 0.05%; ModuloDeRuptura: > 45 N/mm²; ResistenciaAFlexao: >3500 N; ResistenciaAAbrasaoProfunda: < 120 mm³; DilatacaoTermicaLinear: ≤ 8,0x10-6 °C-1; ResistenciaAoChoqueTermico: Resiste; DurabilidadeResistenciaAoGeloDegelo: Resiste; ResistenciaAoEscorregamentoDIN51130: R11; ResistenciaAoEscorregamentoDIN51097: B; ResistenciaAoEscorregamentoENV51097: B; ResistenciaAoEscorregamentoENV12633: Class 2; ResistenciaAoEscorregamentoBS7976: >36; ResistenciaAoEscorregamentoANSIA1371: ≥0,42; ResistenciaAoDeslizamentoENV12633: Class 2; ResistenciaAoDeslizamentoBS7976: >36; ResistenciaAsManchas: Class 5; ResistenciaABaixasConcentracoesDeAcidosEAlcalis: Classe LA; ResistenciaAAltasConcentracoesDeAcidosEAlcalis: Classe HA; LibertacaoDeCadmio: 0; LibertacaoDeChumbo: 0
Type - IFC.REVIGRÉS-Dados de especificação-Floor Covering - VariacaoTonalidade: 3; NivelDeTrafego: 5; EPavimento: Sim; ERevestimento: Sim; EExterno: Sim
Type - IFC.REVIGRÉS-Dados geométricos-Floor Covering - AlturaNominal: 11.2 mm; ComprimentoNominal: 19.6 mm; LarguraNominal: 178 mm
Type - IFC.REVIGRÉS-Dados de sustentabilidade-Floor Covering - ItemEParcialmenteReciclado: 0; EnergiaTermicaExportada: 0; ItemENovo: Sim; ItemEReciclado: Não; VidaÚtilEsperada: 50; SubstanciasPerigosas: Não; PotencialDeEsgotamentoAbioticoDosRecursosFosseis: 203; PotencialDeEsgotamentoAbioticoDosRecursosNaoFosseisMineraisEMetais: 0.000701; PotencialDeAquecimentoGlobalBiogenico: -0.48; CombustiveisFosseisComPotencialDeAquecimentoGlobal: 13.9; PotencialDeAquecimentoGlobalUsoDoSoloEMudancaDeUsoDoSolo: 0.0246; PotencialDeEutrofizacaoFraccaoDeNutrientesQueAtingemOCompartimentoFinalDeAguaDoce: 0.000189; PotencialDeEutrofizacaoFraccaoDeNutrientesQueAtingemOCompartimentoFinalMarinho: 0.0122; EnergiaRecuperada: 0.00739; ConsumoDeAguaDoce: 0.113; UtilizacaoLiquidaDeAguaDoce: 0.113; ResiduosPerigososEliminados: 0.00221; ResiduosNaoPerigososEliminados: 1.83; MassaTotalDeResiduosRadioactivosEliminados: 0.000394; EnergiaElectricaExportada: 1.55; MateriaisParaRecuperacaoDeEnergia: 0.00739; MateriaisParaReciclagem: 0.0253; UnidadeEPD: 1 m²
Type - IFC.REVIGRÉS-Dados gerais-Floor Covering - Nome: REVIGRÉS-RULE-BASE-19.6X178-SOFT GRIP-ALLOY; TipoProduto: Prensado a seco: grupo BIa UGL | Grés porcelânico técnico; NumeroDeRegistoDAP: EPD-REV-20240006-CCC1-EN; ReferenciaDAP: -; UrlDOP: -
Classification: C3020 (Uniformat)
Pset_CoveringCommon - TotalThickness: 11.2 mm
IFC.REVIGRÉS-Dados do fabricante-Floor Covering - Type: Floor: REVIGRÉS-RULE-BASE-19,6x178-SOFT GRIP-ALLOY
IFC.REVIGRÉS-Dados de desempenho-Floor Covering - Type: Floor: REVIGRÉS-RULE-BASE-19,6x178-SOFT GRIP-ALLOY
IFC.REVIGRÉS-Dados de especificação-Floor Covering - Type: Floor: REVIGRÉS-RULE-BASE-19,6x178-SOFT GRIP-ALLOY
IFC.REVIGRÉS-Dados geométricos-Floor Covering - Type: Floor: REVIGRÉS-RULE-BASE-19,6x178-SOFT GRIP-ALLOY
IFC.REVIGRÉS-Dados de sustentabilidade-Floor Covering - Type: Floor: REVIGRÉS-RULE-BASE-19,6x178-SOFT GRIP-ALLOY

# IfcCovering: Floor:REVIGRÉS-RULE-BASE-19,6x178-SOFT GRIP-SMOG, Floor:REVIGRÉS-RULE-BASE-19,6x178-SOFT GRIP-SMOG:11517
In: Level 1
Type - PredefinedType: FLOORING; Material: REVIGRÉS-RULE-BASE-19.6x178-SOFT GRIP-SMOG 11.2 mm
Type - Pset_CoveringCommon - Reference: 312FS8V721; Material: Grés porcelânico
Type - Pset_ElementShading - Roughness: 304.8 mm
Type - Pset_ManufacturerTypeInformation - Manufacturer: REVIGRÉS
Type - Pset_ProductRequirements - Category: Floors
Type - Pset_QuantityTakeOff - Reference: 312FS8V721
Type - IFC.REVIGRÉS-Dados do fabricante-Floor Covering - FabricanteURL: https://www.revigres.pt/; ReferenciaModelo: Rule; NumeroGlobalDeItemComercial: 312FS8V721; Acabamento: SOFT GRIP; Material: Grés porcelânico; IdentificadorDoOperadorEconomico: 501840856; UrlFabricanteArtigo: https://www.revigres.pt/colecoes/rule; PaisOrigem: Portugal
Type - IFC.REVIGRÉS-Dados de desempenho-Floor Covering - Rectilinearidade: ± 0.2% máx.± 0.8 mm; Ortogonalidade: ± 0.2% máx.± 1.5 mm; PlanaridadeDaSuperficie: ± 0.3% máx. ± 1.8 mm; QualidadeDaSuperficie: Cumpre; AbsorcaoDeAgua: < 0.05%; ModuloDeRuptura: > 45 N/mm²; ResistenciaAFlexao: >3500 N; ResistenciaAAbrasaoProfunda: < 120 mm³; DilatacaoTermicaLinear: ≤ 8,0x10-6 °C-1; ResistenciaAoChoqueTermico: Resiste; DurabilidadeResistenciaAoGeloDegelo: Resiste; ResistenciaAoEscorregamentoDIN51130: R11; ResistenciaAoEscorregamentoDIN51097: B; ResistenciaAoEscorregamentoENV51097: B; ResistenciaAoEscorregamentoENV12633: Class 2; ResistenciaAoEscorregamentoBS7976: >36; ResistenciaAoEscorregamentoANSIA1371: ≥0,42; ResistenciaAoDeslizamentoENV12633: Class 2; ResistenciaAoDeslizamentoBS7976: >36; ResistenciaAsManchas: Class 5; ResistenciaABaixasConcentracoesDeAcidosEAlcalis: Classe LA; ResistenciaAAltasConcentracoesDeAcidosEAlcalis: Classe HA; LibertacaoDeCadmio: 0; LibertacaoDeChumbo: 0
Type - IFC.REVIGRÉS-Dados de especificação-Floor Covering - VariacaoTonalidade: 3; NivelDeTrafego: 5; EPavimento: Sim; ERevestimento: Sim; EExterno: Sim
Type - IFC.REVIGRÉS-Dados geométricos-Floor Covering - AlturaNominal: 11.2 mm; ComprimentoNominal: 19.6 mm; LarguraNominal: 178 mm
Type - IFC.REVIGRÉS-Dados de sustentabilidade-Floor Covering - EnergiaTermicaExportada: 0; ItemENovo: Sim; ItemEParcialmenteReciclado: 0.23; ItemEReciclado: Sim; VidaÚtilEsperada: 50; SubstanciasPerigosas: Não; PotencialDeEsgotamentoAbioticoDosRecursosFosseis: 203; PotencialDeEsgotamentoAbioticoDosRecursosNaoFosseisMineraisEMetais: 0.000701; PotencialDeAquecimentoGlobalBiogenico: -0.48; CombustiveisFosseisComPotencialDeAquecimentoGlobal: 13.9; PotencialDeAquecimentoGlobalUsoDoSoloEMudancaDeUsoDoSolo: 0.0246; PotencialDeEutrofizacaoFraccaoDeNutrientesQueAtingemOCompartimentoFinalDeAguaDoce: 0.000189; PotencialDeEutrofizacaoFraccaoDeNutrientesQueAtingemOCompartimentoFinalMarinho: 0.0122; EnergiaRecuperada: 0.00739; ConsumoDeAguaDoce: 0.113; UtilizacaoLiquidaDeAguaDoce: 0.113; ResiduosPerigososEliminados: 0.00221; ResiduosNaoPerigososEliminados: 1.83; MassaTotalDeResiduosRadioactivosEliminados: 0.000394; EnergiaElectricaExportada: 1.55; MateriaisParaRecuperacaoDeEnergia: 0.00739; MateriaisParaReciclagem: 0.0253; UnidadeEPD: 1 m²
Type - IFC.REVIGRÉS-Dados gerais-Floor Covering - Nome: REVIGRÉS-RULE-BASE-19.6X178-SOFT GRIP-SMOG; TipoProduto: Prensado a seco: grupo BIa UGL | Grés porcelânico técnico; NumeroDeRegistoDAP: EPD-REV-20240006-CCC1-EN; ReferenciaDAP: -; UrlDOP: -
Classification: C3020 (Uniformat)
Pset_CoveringCommon - TotalThickness: 11.2 mm
IFC.REVIGRÉS-Dados do fabricante-Floor Covering - Type: Floor: REVIGRÉS-RULE-BASE-19,6x178-SOFT GRIP-SMOG
IFC.REVIGRÉS-Dados de desempenho-Floor Covering - Type: Floor: REVIGRÉS-RULE-BASE-19,6x178-SOFT GRIP-SMOG
IFC.REVIGRÉS-Dados de especificação-Floor Covering - Type: Floor: REVIGRÉS-RULE-BASE-19,6x178-SOFT GRIP-SMOG
IFC.REVIGRÉS-Dados geométricos-Floor Covering - Type: Floor: REVIGRÉS-RULE-BASE-19,6x178-SOFT GRIP-SMOG
IFC.REVIGRÉS-Dados de sustentabilidade-Floor Covering - Type: Floor: REVIGRÉS-RULE-BASE-19,6x178-SOFT GRIP-SMOG

# IfcCovering: Floor:REVIGRÉS-RULE-BASE-29,5x118,6-SILK-ALLOY, Floor:REVIGRÉS-RULE-BASE-29,5x118,6-SILK-ALLOY:11621
In: Level 1
Type - PredefinedType: FLOORING; Material: REVIGRÉS-RULE-BASE-29.5x118.6-SILK-ALLOY 10.5 mm
Type - Pset_CoveringCommon - Reference: 312GD6V711; Material: Grés porcelânico
Type - Pset_ElementShading - Roughness: 304.8 mm
Type - Pset_ManufacturerTypeInformation - Manufacturer: REVIGRÉS
Type - Pset_ProductRequirements - Category: Floors
Type - Pset_QuantityTakeOff - Reference: 312GD6V711
Type - IFC.REVIGRÉS-Dados do fabricante-Floor Covering - FabricanteURL: https://www.revigres.pt/; ReferenciaModelo: Rule; NumeroGlobalDeItemComercial: 312GD6V711; Acabamento: SILK; Material: Grés porcelânico; IdentificadorDoOperadorEconomico: 501840856; UrlFabricanteArtigo: https://www.revigres.pt/colecoes/rule; PaisOrigem: Portugal
Type - IFC.REVIGRÉS-Dados de desempenho-Floor Covering - Rectilinearidade: ± 0.2% máx.± 0.8 mm; Ortogonalidade: ± 0.2% máx.± 1.5 mm; PlanaridadeDaSuperficie: ± 0.3% máx. ± 1.8 mm; QualidadeDaSuperficie: Cumpre; AbsorcaoDeAgua: < 0.05%; ModuloDeRuptura: > 45 N/mm²; ResistenciaAFlexao: >3500 N; ResistenciaAAbrasaoProfunda: < 120 mm³; DilatacaoTermicaLinear: ≤ 8,0x10-6 °C-1; ResistenciaAoChoqueTermico: Resiste; DurabilidadeResistenciaAoGeloDegelo: Resiste; ResistenciaAoEscorregamentoDIN51130: R9; ResistenciaAoEscorregamentoDIN51097: A; ResistenciaAoEscorregamentoENV51097: A; ResistenciaAoEscorregamentoENV12633: Class 1; ResistenciaAoEscorregamentoANSIA1371: ≥0,42; ResistenciaAoDeslizamentoENV12633: Class 1; ResistenciaAsManchas: Class 5; ResistenciaABaixasConcentracoesDeAcidosEAlcalis: Classe LA; ResistenciaAAltasConcentracoesDeAcidosEAlcalis: Classe HA; LibertacaoDeCadmio: 0; LibertacaoDeChumbo: 0
Type - IFC.REVIGRÉS-Dados de especificação-Floor Covering - VariacaoTonalidade: 3; NivelDeTrafego: 5; EPavimento: Sim; ERevestimento: Sim; EExterno: Sim
Type - IFC.REVIGRÉS-Dados geométricos-Floor Covering - AlturaNominal: 10.5 mm; ComprimentoNominal: 29.5 mm; LarguraNominal: 118.6 mm
Type - IFC.REVIGRÉS-Dados de sustentabilidade-Floor Covering - ItemEParcialmenteReciclado: 0; EnergiaTermicaExportada: 0; ItemENovo: Sim; ItemEReciclado: Não; VidaÚtilEsperada: 50; SubstanciasPerigosas: Não; PotencialDeEsgotamentoAbioticoDosRecursosFosseis: 203; PotencialDeEsgotamentoAbioticoDosRecursosNaoFosseisMineraisEMetais: 0.000701; PotencialDeAquecimentoGlobalBiogenico: -0.48; CombustiveisFosseisComPotencialDeAquecimentoGlobal: 13.9; PotencialDeAquecimentoGlobalUsoDoSoloEMudancaDeUsoDoSolo: 0.0246; PotencialDeEutrofizacaoFraccaoDeNutrientesQueAtingemOCompartimentoFinalDeAguaDoce: 0.000189; PotencialDeEutrofizacaoFraccaoDeNutrientesQueAtingemOCompartimentoFinalMarinho: 0.0122; EnergiaRecuperada: 0.00739; ConsumoDeAguaDoce: 0.113; UtilizacaoLiquidaDeAguaDoce: 0.113; ResiduosPerigososEliminados: 0.00221; ResiduosNaoPerigososEliminados: 1.83; MassaTotalDeResiduosRadioactivosEliminados: 0.000394; EnergiaElectricaExportada: 1.55; MateriaisParaRecuperacaoDeEnergia: 0.00739; MateriaisParaReciclagem: 0.0253; UnidadeEPD: 1 m²
Type - IFC.REVIGRÉS-Dados gerais-Floor Covering - Nome: REVIGRÉS-RULE-BASE-29.5X118.6-SILK-ALLOY; TipoProduto: Prensado a seco: grupo BIa UGL | Grés porcelânico técnico; NumeroDeRegistoDAP: EPD-REV-20240006-CCC1-EN; ReferenciaDAP: -; UrlDOP: -
Classification: C3020 (Uniformat)
Pset_CoveringCommon - TotalThickness: 10.5 mm
IFC.REVIGRÉS-Dados do fabricante-Floor Covering - Type: Floor: REVIGRÉS-RULE-BASE-29,5x118,6-SILK-ALLOY
IFC.REVIGRÉS-Dados de desempenho-Floor Covering - Type: Floor: REVIGRÉS-RULE-BASE-29,5x118,6-SILK-ALLOY
IFC.REVIGRÉS-Dados de especificação-Floor Covering - Type: Floor: REVIGRÉS-RULE-BASE-29,5x118,6-SILK-ALLOY
IFC.REVIGRÉS-Dados geométricos-Floor Covering - Type: Floor: REVIGRÉS-RULE-BASE-29,5x118,6-SILK-ALLOY
IFC.REVIGRÉS-Dados de sustentabilidade-Floor Covering - Type: Floor: REVIGRÉS-RULE-BASE-29,5x118,6-SILK-ALLOY

# IfcCovering: Floor:REVIGRÉS-RULE-BASE-29,5x118,6-SILK-SMOG, Floor:REVIGRÉS-RULE-BASE-29,5x118,6-SILK-SMOG:12138
In: Level 1
Type - PredefinedType: FLOORING; Material: REVIGRÉS-RULE-BASE-29.5x118.6-SILK-SMOG 10.5 mm
Type - Pset_CoveringCommon - Reference: 312GD6V721; Material: Grés porcelânico
Type - Pset_ElementShading - Roughness: 304.8 mm
Type - Pset_ManufacturerTypeInformation - Manufacturer: REVIGRÉS
Type - Pset_ProductRequirements - Category: Floors
Type - Pset_QuantityTakeOff - Reference: 312GD6V721
Type - IFC.REVIGRÉS-Dados do fabricante-Floor Covering - FabricanteURL: https://www.revigres.pt/; ReferenciaModelo: Rule; NumeroGlobalDeItemComercial: 312GD6V721; Acabamento: SILK; Material: Grés porcelânico; IdentificadorDoOperadorEconomico: 501840856; UrlFabricanteArtigo: https://www.revigres.pt/colecoes/rule; PaisOrigem: Portugal
Type - IFC.REVIGRÉS-Dados de desempenho-Floor Covering - Rectilinearidade: ± 0.2% máx.± 0.8 mm; Ortogonalidade: ± 0.2% máx.± 1.5 mm; PlanaridadeDaSuperficie: ± 0.3% máx. ± 1.8 mm; QualidadeDaSuperficie: Cumpre; AbsorcaoDeAgua: < 0.05%; ModuloDeRuptura: > 45 N/mm²; ResistenciaAFlexao: >3500 N; ResistenciaAAbrasaoProfunda: < 120 mm³; DilatacaoTermicaLinear: ≤ 8,0x10-6 °C-1; ResistenciaAoChoqueTermico: Resiste; DurabilidadeResistenciaAoGeloDegelo: Resiste; ResistenciaAoEscorregamentoDIN51130: R9; ResistenciaAoEscorregamentoDIN51097: A; ResistenciaAoEscorregamentoENV51097: A; ResistenciaAoEscorregamentoENV12633: Class 1; ResistenciaAoEscorregamentoANSIA1371: ≥0,42; ResistenciaAoDeslizamentoENV12633: Class 1; ResistenciaAsManchas: Class 5; ResistenciaABaixasConcentracoesDeAcidosEAlcalis: Classe LA; ResistenciaAAltasConcentracoesDeAcidosEAlcalis: Classe HA; LibertacaoDeCadmio: 0; LibertacaoDeChumbo: 0
Type - IFC.REVIGRÉS-Dados de especificação-Floor Covering - VariacaoTonalidade: 3; NivelDeTrafego: 5; EPavimento: Sim; ERevestimento: Sim; EExterno: Sim
Type - IFC.REVIGRÉS-Dados geométricos-Floor Covering - AlturaNominal: 10.5 mm; ComprimentoNominal: 29.5 mm; LarguraNominal: 118.6 mm
Type - IFC.REVIGRÉS-Dados de sustentabilidade-Floor Covering - EnergiaTermicaExportada: 0; ItemENovo: Sim; ItemEParcialmenteReciclado: 0.23; ItemEReciclado: Sim; VidaÚtilEsperada: 50; SubstanciasPerigosas: Não; PotencialDeEsgotamentoAbioticoDosRecursosFosseis: 203; PotencialDeEsgotamentoAbioticoDosRecursosNaoFosseisMineraisEMetais: 0.000701; PotencialDeAquecimentoGlobalBiogenico: -0.48; CombustiveisFosseisComPotencialDeAquecimentoGlobal: 13.9; PotencialDeAquecimentoGlobalUsoDoSoloEMudancaDeUsoDoSolo: 0.0246; PotencialDeEutrofizacaoFraccaoDeNutrientesQueAtingemOCompartimentoFinalDeAguaDoce: 0.000189; PotencialDeEutrofizacaoFraccaoDeNutrientesQueAtingemOCompartimentoFinalMarinho: 0.0122; EnergiaRecuperada: 0.00739; ConsumoDeAguaDoce: 0.113; UtilizacaoLiquidaDeAguaDoce: 0.113; ResiduosPerigososEliminados: 0.00221; ResiduosNaoPerigososEliminados: 1.83; MassaTotalDeResiduosRadioactivosEliminados: 0.000394; EnergiaElectricaExportada: 1.55; MateriaisParaRecuperacaoDeEnergia: 0.00739; MateriaisParaReciclagem: 0.0253; UnidadeEPD: 1 m²
Type - IFC.REVIGRÉS-Dados gerais-Floor Covering - Nome: REVIGRÉS-RULE-BASE-29.5X118.6-SILK-SMOG; TipoProduto: Prensado a seco: grupo BIa UGL | Grés porcelânico técnico; NumeroDeRegistoDAP: EPD-REV-20240006-CCC1-EN; ReferenciaDAP: -; UrlDOP: -
Classification: C3020 (Uniformat)
Pset_CoveringCommon - TotalThickness: 10.5 mm
IFC.REVIGRÉS-Dados do fabricante-Floor Covering - Type: Floor: REVIGRÉS-RULE-BASE-29,5x118,6-SILK-SMOG
IFC.REVIGRÉS-Dados de desempenho-Floor Covering - Type: Floor: REVIGRÉS-RULE-BASE-29,5x118,6-SILK-SMOG
IFC.REVIGRÉS-Dados de especificação-Floor Covering - Type: Floor: REVIGRÉS-RULE-BASE-29,5x118,6-SILK-SMOG
IFC.REVIGRÉS-Dados geométricos-Floor Covering - Type: Floor: REVIGRÉS-RULE-BASE-29,5x118,6-SILK-SMOG
IFC.REVIGRÉS-Dados de sustentabilidade-Floor Covering - Type: Floor: REVIGRÉS-RULE-BASE-29,5x118,6-SILK-SMOG

# IfcCovering: Floor:REVIGRÉS-RULE-BASE-29,5x118,6-SOFT GRIP-ALLOY, Floor:REVIGRÉS-RULE-BASE-29,5x118,6-SOFT GRIP-ALLOY:11684
In: Level 1
Type - PredefinedType: FLOORING; Material: REVIGRÉS-RULE-BASE-29.5x118.6-SOFT GRIP-ALLOY 10.5 mm
Type - Pset_CoveringCommon - Reference: 312FD6V711; Material: Grés porcelânico
Type - Pset_ElementShading - Roughness: 304.8 mm
Type - Pset_ManufacturerTypeInformation - Manufacturer: REVIGRÉS
Type - Pset_ProductRequirements - Category: Floors
Type - Pset_QuantityTakeOff - Reference: 312FD6V711
Type - IFC.REVIGRÉS-Dados do fabricante-Floor Covering - FabricanteURL: https://www.revigres.pt/; ReferenciaModelo: Rule; NumeroGlobalDeItemComercial: 312FD6V711; Acabamento: SOFT GRIP; Material: Grés porcelânico; IdentificadorDoOperadorEconomico: 501840856; UrlFabricanteArtigo: https://www.revigres.pt/colecoes/rule; PaisOrigem: Portugal
Type - IFC.REVIGRÉS-Dados de desempenho-Floor Covering - Rectilinearidade: ± 0.2% máx.± 0.8 mm; Ortogonalidade: ± 0.2% máx.± 1.5 mm; PlanaridadeDaSuperficie: ± 0.3% máx. ± 1.8 mm; QualidadeDaSuperficie: Cumpre; AbsorcaoDeAgua: < 0.05%; ModuloDeRuptura: > 45 N/mm²; ResistenciaAFlexao: >3500 N; ResistenciaAAbrasaoProfunda: < 120 mm³; DilatacaoTermicaLinear: ≤ 8,0x10-6 °C-1; ResistenciaAoChoqueTermico: Resiste; DurabilidadeResistenciaAoGeloDegelo: Resiste; ResistenciaAoEscorregamentoDIN51130: R11; ResistenciaAoEscorregamentoDIN51097: B; ResistenciaAoEscorregamentoENV51097: B; ResistenciaAoEscorregamentoENV12633: Class 2; ResistenciaAoEscorregamentoBS7976: >36; ResistenciaAoEscorregamentoANSIA1371: ≥0,42; ResistenciaAoDeslizamentoENV12633: Class 2; ResistenciaAoDeslizamentoBS7976: >36; ResistenciaAsManchas: Class 5; ResistenciaABaixasConcentracoesDeAcidosEAlcalis: Classe LA; ResistenciaAAltasConcentracoesDeAcidosEAlcalis: Classe HA; LibertacaoDeCadmio: 0; LibertacaoDeChumbo: 0
Type - IFC.REVIGRÉS-Dados de especificação-Floor Covering - VariacaoTonalidade: 3; NivelDeTrafego: 5; EPavimento: Sim; ERevestimento: Sim; EExterno: Sim
Type - IFC.REVIGRÉS-Dados geométricos-Floor Covering - AlturaNominal: 10.5 mm; ComprimentoNominal: 29.5 mm; LarguraNominal: 118.6 mm
Type - IFC.REVIGRÉS-Dados de sustentabilidade-Floor Covering - ItemEParcialmenteReciclado: 0; EnergiaTermicaExportada: 0; ItemENovo: Sim; ItemEReciclado: Não; VidaÚtilEsperada: 50; SubstanciasPerigosas: Não; PotencialDeEsgotamentoAbioticoDosRecursosFosseis: 203; PotencialDeEsgotamentoAbioticoDosRecursosNaoFosseisMineraisEMetais: 0.000701; PotencialDeAquecimentoGlobalBiogenico: -0.48; CombustiveisFosseisComPotencialDeAquecimentoGlobal: 13.9; PotencialDeAquecimentoGlobalUsoDoSoloEMudancaDeUsoDoSolo: 0.0246; PotencialDeEutrofizacaoFraccaoDeNutrientesQueAtingemOCompartimentoFinalDeAguaDoce: 0.000189; PotencialDeEutrofizacaoFraccaoDeNutrientesQueAtingemOCompartimentoFinalMarinho: 0.0122; EnergiaRecuperada: 0.00739; ConsumoDeAguaDoce: 0.113; UtilizacaoLiquidaDeAguaDoce: 0.113; ResiduosPerigososEliminados: 0.00221; ResiduosNaoPerigososEliminados: 1.83; MassaTotalDeResiduosRadioactivosEliminados: 0.000394; EnergiaElectricaExportada: 1.55; MateriaisParaRecuperacaoDeEnergia: 0.00739; MateriaisParaReciclagem: 0.0253; UnidadeEPD: 1 m²
Type - IFC.REVIGRÉS-Dados gerais-Floor Covering - Nome: REVIGRÉS-RULE-BASE-29.5X118.6-SOFT GRIP-ALLOY; TipoProduto: Prensado a seco: grupo BIa UGL | Grés porcelânico técnico; NumeroDeRegistoDAP: EPD-REV-20240006-CCC1-EN; ReferenciaDAP: -; UrlDOP: -
Classification: C3020 (Uniformat)
Pset_CoveringCommon - TotalThickness: 10.5 mm
IFC.REVIGRÉS-Dados do fabricante-Floor Covering - Type: Floor: REVIGRÉS-RULE-BASE-29,5x118,6-SOFT GRIP-ALLOY
IFC.REVIGRÉS-Dados de desempenho-Floor Covering - Type: Floor: REVIGRÉS-RULE-BASE-29,5x118,6-SOFT GRIP-ALLOY
IFC.REVIGRÉS-Dados de especificação-Floor Covering - Type: Floor: REVIGRÉS-RULE-BASE-29,5x118,6-SOFT GRIP-ALLOY
IFC.REVIGRÉS-Dados geométricos-Floor Covering - Type: Floor: REVIGRÉS-RULE-BASE-29,5x118,6-SOFT GRIP-ALLOY
IFC.REVIGRÉS-Dados de sustentabilidade-Floor Covering - Type: Floor: REVIGRÉS-RULE-BASE-29,5x118,6-SOFT GRIP-ALLOY

# IfcCovering: Floor:REVIGRÉS-RULE-BASE-29,5x118,6-SOFT GRIP-SMOG, Floor:REVIGRÉS-RULE-BASE-29,5x118,6-SOFT GRIP-SMOG:12147
In: Level 1
Type - PredefinedType: FLOORING; Material: REVIGRÉS-RULE-BASE-29.5x118.6-SOFT GRIP-SMOG 10.5 mm
Type - Pset_CoveringCommon - Reference: 312FD6V721; Material: Grés porcelânico
Type - Pset_ElementShading - Roughness: 304.8 mm
Type - Pset_ManufacturerTypeInformation - Manufacturer: REVIGRÉS
Type - Pset_ProductRequirements - Category: Floors
Type - Pset_QuantityTakeOff - Reference: 312FD6V721
Type - IFC.REVIGRÉS-Dados do fabricante-Floor Covering - FabricanteURL: https://www.revigres.pt/; ReferenciaModelo: Rule; NumeroGlobalDeItemComercial: 312FD6V721; Acabamento: SOFT GRIP; Material: Grés porcelânico; IdentificadorDoOperadorEconomico: 501840856; UrlFabricanteArtigo: https://www.revigres.pt/colecoes/rule; PaisOrigem: Portugal
Type - IFC.REVIGRÉS-Dados de desempenho-Floor Covering - Rectilinearidade: ± 0.2% máx.± 0.8 mm; Ortogonalidade: ± 0.2% máx.± 1.5 mm; PlanaridadeDaSuperficie: ± 0.3% máx. ± 1.8 mm; QualidadeDaSuperficie: Cumpre; AbsorcaoDeAgua: < 0.05%; ModuloDeRuptura: > 45 N/mm²; ResistenciaAFlexao: >3500 N; ResistenciaAAbrasaoProfunda: < 120 mm³; DilatacaoTermicaLinear: ≤ 8,0x10-6 °C-1; ResistenciaAoChoqueTermico: Resiste; DurabilidadeResistenciaAoGeloDegelo: Resiste; ResistenciaAoEscorregamentoDIN51130: R11; ResistenciaAoEscorregamentoDIN51097: B; ResistenciaAoEscorregamentoENV51097: B; ResistenciaAoEscorregamentoENV12633: Class 2; ResistenciaAoEscorregamentoBS7976: >36; ResistenciaAoEscorregamentoANSIA1371: ≥0,42; ResistenciaAoDeslizamentoENV12633: Class 2; ResistenciaAoDeslizamentoBS7976: >36; ResistenciaAsManchas: Class 5; ResistenciaABaixasConcentracoesDeAcidosEAlcalis: Classe LA; ResistenciaAAltasConcentracoesDeAcidosEAlcalis: Classe HA; LibertacaoDeCadmio: 0; LibertacaoDeChumbo: 0
Type - IFC.REVIGRÉS-Dados de especificação-Floor Covering - VariacaoTonalidade: 3; NivelDeTrafego: 5; EPavimento: Sim; ERevestimento: Sim; EExterno: Sim
Type - IFC.REVIGRÉS-Dados geométricos-Floor Covering - AlturaNominal: 10.5 mm; ComprimentoNominal: 29.5 mm; LarguraNominal: 118.6 mm
Type - IFC.REVIGRÉS-Dados de sustentabilidade-Floor Covering - EnergiaTermicaExportada: 0; ItemENovo: Sim; ItemEParcialmenteReciclado: 0.23; ItemEReciclado: Sim; VidaÚtilEsperada: 50; SubstanciasPerigosas: Não; PotencialDeEsgotamentoAbioticoDosRecursosFosseis: 203; PotencialDeEsgotamentoAbioticoDosRecursosNaoFosseisMineraisEMetais: 0.000701; PotencialDeAquecimentoGlobalBiogenico: -0.48; CombustiveisFosseisComPotencialDeAquecimentoGlobal: 13.9; PotencialDeAquecimentoGlobalUsoDoSoloEMudancaDeUsoDoSolo: 0.0246; PotencialDeEutrofizacaoFraccaoDeNutrientesQueAtingemOCompartimentoFinalDeAguaDoce: 0.000189; PotencialDeEutrofizacaoFraccaoDeNutrientesQueAtingemOCompartimentoFinalMarinho: 0.0122; EnergiaRecuperada: 0.00739; ConsumoDeAguaDoce: 0.113; UtilizacaoLiquidaDeAguaDoce: 0.113; ResiduosPerigososEliminados: 0.00221; ResiduosNaoPerigososEliminados: 1.83; MassaTotalDeResiduosRadioactivosEliminados: 0.000394; EnergiaElectricaExportada: 1.55; MateriaisParaRecuperacaoDeEnergia: 0.00739; MateriaisParaReciclagem: 0.0253; UnidadeEPD: 1 m²
Type - IFC.REVIGRÉS-Dados gerais-Floor Covering - Nome: REVIGRÉS-RULE-BASE-29.5X118.6-SOFT GRIP-SMOG; TipoProduto: Prensado a seco: grupo BIa UGL | Grés porcelânico técnico; NumeroDeRegistoDAP: EPD-REV-20240006-CCC1-EN; ReferenciaDAP: -; UrlDOP: -
Classification: C3020 (Uniformat)
Pset_CoveringCommon - TotalThickness: 10.5 mm
IFC.REVIGRÉS-Dados do fabricante-Floor Covering - Type: Floor: REVIGRÉS-RULE-BASE-29,5x118,6-SOFT GRIP-SMOG
IFC.REVIGRÉS-Dados de desempenho-Floor Covering - Type: Floor: REVIGRÉS-RULE-BASE-29,5x118,6-SOFT GRIP-SMOG
IFC.REVIGRÉS-Dados de especificação-Floor Covering - Type: Floor: REVIGRÉS-RULE-BASE-29,5x118,6-SOFT GRIP-SMOG
IFC.REVIGRÉS-Dados geométricos-Floor Covering - Type: Floor: REVIGRÉS-RULE-BASE-29,5x118,6-SOFT GRIP-SMOG
IFC.REVIGRÉS-Dados de sustentabilidade-Floor Covering - Type: Floor: REVIGRÉS-RULE-BASE-29,5x118,6-SOFT GRIP-SMOG

# IfcCovering: Floor:REVIGRÉS-RULE-BASE-29,5x178-SILK-ALLOY, Floor:REVIGRÉS-RULE-BASE-29,5x178-SILK-ALLOY:11762
In: Level 1
Type - PredefinedType: FLOORING; Material: REVIGRÉS-RULE-BASE-29.5x178-SILK-ALLOY 11.2 mm
Type - Pset_CoveringCommon - Reference: 312GS7V711; Material: Grés porcelânico
Type - Pset_ElementShading - Roughness: 304.8 mm
Type - Pset_ManufacturerTypeInformation - Manufacturer: REVIGRÉS
Type - Pset_ProductRequirements - Category: Floors
Type - Pset_QuantityTakeOff - Reference: 312GS7V711
Type - IFC.REVIGRÉS-Dados do fabricante-Floor Covering - FabricanteURL: https://www.revigres.pt/; ReferenciaModelo: Rule; NumeroGlobalDeItemComercial: 312GS7V711; Acabamento: SILK; Material: Grés porcelânico; IdentificadorDoOperadorEconomico: 501840856; UrlFabricanteArtigo: https://www.revigres.pt/colecoes/rule; PaisOrigem: Portugal
Type - IFC.REVIGRÉS-Dados de desempenho-Floor Covering - Rectilinearidade: ± 0.2% máx.± 0.8 mm; Ortogonalidade: ± 0.2% máx.± 1.5 mm; PlanaridadeDaSuperficie: ± 0.3% máx. ± 1.8 mm; QualidadeDaSuperficie: Cumpre; AbsorcaoDeAgua: < 0.05%; ModuloDeRuptura: > 45 N/mm²; ResistenciaAFlexao: >3500 N; ResistenciaAAbrasaoProfunda: < 120 mm³; DilatacaoTermicaLinear: ≤ 8,0x10-6 °C-1; ResistenciaAoChoqueTermico: Resiste; DurabilidadeResistenciaAoGeloDegelo: Resiste; ResistenciaAoEscorregamentoDIN51130: R9; ResistenciaAoEscorregamentoDIN51097: A; ResistenciaAoEscorregamentoENV51097: A; ResistenciaAoEscorregamentoENV12633: Class 1; ResistenciaAoEscorregamentoANSIA1371: ≥0,42; ResistenciaAoDeslizamentoENV12633: Class 1; ResistenciaAsManchas: Class 5; ResistenciaABaixasConcentracoesDeAcidosEAlcalis: Classe LA; ResistenciaAAltasConcentracoesDeAcidosEAlcalis: Classe HA; LibertacaoDeCadmio: 0; LibertacaoDeChumbo: 0
Type - IFC.REVIGRÉS-Dados de especificação-Floor Covering - VariacaoTonalidade: 3; NivelDeTrafego: 5; EPavimento: Sim; ERevestimento: Sim; EExterno: Sim
Type - IFC.REVIGRÉS-Dados geométricos-Floor Covering - AlturaNominal: 11.2 mm; ComprimentoNominal: 29.5 mm; LarguraNominal: 178 mm
Type - IFC.REVIGRÉS-Dados de sustentabilidade-Floor Covering - ItemEParcialmenteReciclado: 0; EnergiaTermicaExportada: 0; ItemENovo: Sim; ItemEReciclado: Não; VidaÚtilEsperada: 50; SubstanciasPerigosas: Não; PotencialDeEsgotamentoAbioticoDosRecursosFosseis: 203; PotencialDeEsgotamentoAbioticoDosRecursosNaoFosseisMineraisEMetais: 0.000701; PotencialDeAquecimentoGlobalBiogenico: -0.48; CombustiveisFosseisComPotencialDeAquecimentoGlobal: 13.9; PotencialDeAquecimentoGlobalUsoDoSoloEMudancaDeUsoDoSolo: 0.0246; PotencialDeEutrofizacaoFraccaoDeNutrientesQueAtingemOCompartimentoFinalDeAguaDoce: 0.000189; PotencialDeEutrofizacaoFraccaoDeNutrientesQueAtingemOCompartimentoFinalMarinho: 0.0122; EnergiaRecuperada: 0.00739; ConsumoDeAguaDoce: 0.113; UtilizacaoLiquidaDeAguaDoce: 0.113; ResiduosPerigososEliminados: 0.00221; ResiduosNaoPerigososEliminados: 1.83; MassaTotalDeResiduosRadioactivosEliminados: 0.000394; EnergiaElectricaExportada: 1.55; MateriaisParaRecuperacaoDeEnergia: 0.00739; MateriaisParaReciclagem: 0.0253; UnidadeEPD: 1 m²
Type - IFC.REVIGRÉS-Dados gerais-Floor Covering - Nome: REVIGRÉS-RULE-BASE-29.5X178-SILK-ALLOY; TipoProduto: Prensado a seco: grupo BIa UGL | Grés porcelânico técnico; NumeroDeRegistoDAP: EPD-REV-20240006-CCC1-EN; ReferenciaDAP: -; UrlDOP: -
Classification: C3020 (Uniformat)
Pset_CoveringCommon - TotalThickness: 11.2 mm
IFC.REVIGRÉS-Dados do fabricante-Floor Covering - Type: Floor: REVIGRÉS-RULE-BASE-29,5x178-SILK-ALLOY
IFC.REVIGRÉS-Dados de desempenho-Floor Covering - Type: Floor: REVIGRÉS-RULE-BASE-29,5x178-SILK-ALLOY
IFC.REVIGRÉS-Dados de especificação-Floor Covering - Type: Floor: REVIGRÉS-RULE-BASE-29,5x178-SILK-ALLOY
IFC.REVIGRÉS-Dados geométricos-Floor Covering - Type: Floor: REVIGRÉS-RULE-BASE-29,5x178-SILK-ALLOY
IFC.REVIGRÉS-Dados de sustentabilidade-Floor Covering - Type: Floor: REVIGRÉS-RULE-BASE-29,5x178-SILK-ALLOY

# IfcCovering: Floor:REVIGRÉS-RULE-BASE-29,5x178-SILK-SMOG, Floor:REVIGRÉS-RULE-BASE-29,5x178-SILK-SMOG:12156
In: Level 1
Type - PredefinedType: FLOORING; Material: REVIGRÉS-RULE-BASE-29.5x178-SILK-SMOG 11.2 mm
Type - Pset_CoveringCommon - Reference: 312GS7V721; Material: Grés porcelânico
Type - Pset_ElementShading - Roughness: 304.8 mm
Type - Pset_ManufacturerTypeInformation - Manufacturer: REVIGRÉS
Type - Pset_ProductRequirements - Category: Floors
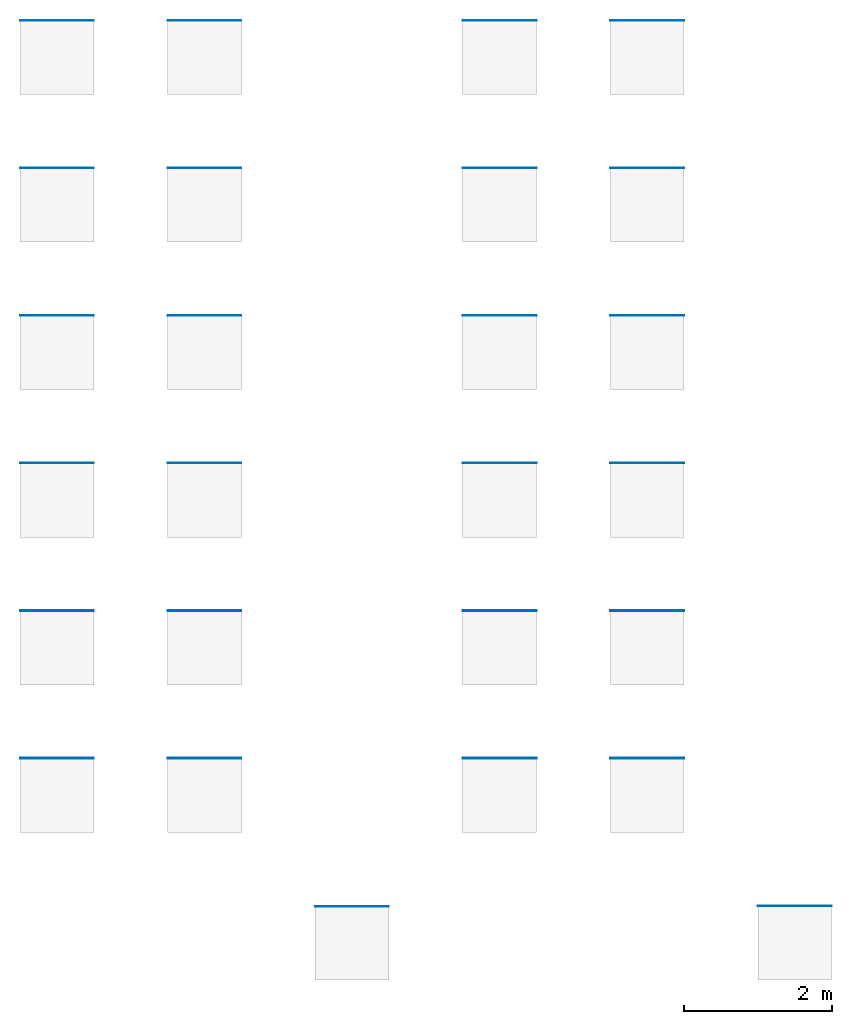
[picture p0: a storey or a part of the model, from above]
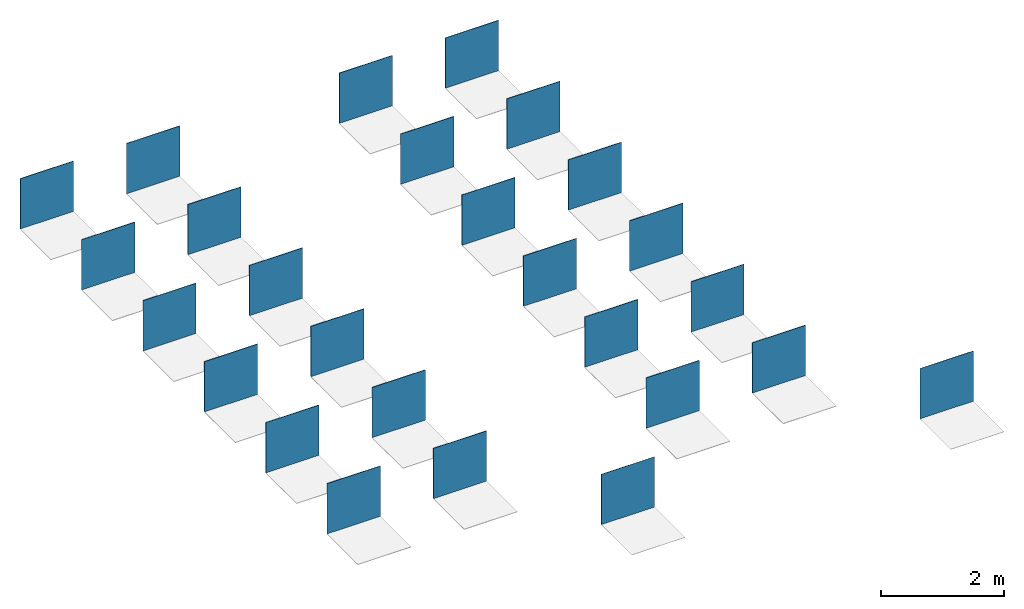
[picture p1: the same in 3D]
Properties of the parts of a building model (IFC2X3), part 4 of 4

# IfcWallStandardCase: Basic Wall:REVIGRÉS-RULE-BASE-59,2x118,6-SILK-ALLOY, Basic Wall:REVIGRÉS-RULE-BASE-59,2x118,6-SILK-ALLOY:11869
Type - IFC.REVIGRÉS-Dados de sustentabilidade-Wall Covering - ItemEParcialmenteReciclado: 0; PotencialPrivacaoDeAguaConsumoDeAguaPonderado: 4.5; EnergiaTermicaExportada: 0; ItemENovo: Sim; ItemEReciclado: Não; VidaÚtilEsperada: 50; SubstanciasPerigosas: Não; PotencialDeEsgotamentoAbioticoDosRecursosFosseis: 203; PotencialDeEsgotamentoAbioticoDosRecursosNaoFosseisMineraisEMetais: 0.000701; PotencialDeAquecimentoGlobalBiogenico: -0.48; CombustiveisFosseisComPotencialDeAquecimentoGlobal: 13.9; PotencialDeAquecimentoGlobalUsoDoSoloEMudancaDeUsoDoSolo: 0.0246; PotencialDeEutrofizacaoFraccaoDeNutrientesQueAtingemOCompartimentoFinalDeAguaDoce: 0.000189; PotencialDeEutrofizacaoFraccaoDeNutrientesQueAtingemOCompartimentoFinalMarinho: 0.0122; EnergiaRecuperada: 0.00739; ConsumoDeAguaDoce: 0.113; UtilizacaoLiquidaDeAguaDoce: 0.113; ResiduosPerigososEliminados: 0.00221; ResiduosNaoPerigososEliminados: 1.83; MassaTotalDeResiduosRadioactivosEliminados: 0.000394; EnergiaElectricaExportada: 1.55; MateriaisParaRecuperacaoDeEnergia: 0.00739; MateriaisParaReciclagem: 0.0253; UnidadeEPD: 1 m²
Type - IFC.REVIGRÉS-Dados gerais-Wall Covering - Nome: REVIGRÉS-RULE-BASE-59.2X118.6-SILK-ALLOY; TipoProduto: Prensado a seco: grupo BIa UGL | Grés porcelânico técnico; NumeroDeRegistoDAP: EPD-REV-20240006-CCC1-EN; ReferenciaDAP: -; UrlDOP: -
Pset_WallCommon - ExtendToStructure: no; LoadBearing: no
IFC.REVIGRÉS-Dados do fabricante-Wall Covering - Type: Basic Wall: REVIGRÉS-RULE-BASE-59,2x118,6-SILK-ALLOY
IFC.REVIGRÉS-Dados de desempenho-Wall Covering - Type: Basic Wall: REVIGRÉS-RULE-BASE-59,2x118,6-SILK-ALLOY
IFC.REVIGRÉS-Dados de especificação-Wall Covering - Type: Basic Wall: REVIGRÉS-RULE-BASE-59,2x118,6-SILK-ALLOY
IFC.REVIGRÉS-Dados geométricos-Wall Covering - Type: Basic Wall: REVIGRÉS-RULE-BASE-59,2x118,6-SILK-ALLOY
IFC.REVIGRÉS-Dados de sustentabilidade-Wall Covering - Type: Basic Wall: REVIGRÉS-RULE-BASE-59,2x118,6-SILK-ALLOY

# IfcWallStandardCase: Basic Wall:REVIGRÉS-RULE-BASE-59,2x118,6-SILK-SMOG, Basic Wall:REVIGRÉS-RULE-BASE-59,2x118,6-SILK-SMOG:12171
In: Level 1
Type - PredefinedType: STANDARD; Material: REVIGRÉS-RULE-BASE-59.2x118.6-SILK-SMOG 10.5 mm
Type - Pset_ElementShading - Roughness: 304.8 mm
Type - Pset_ManufacturerTypeInformation - Manufacturer: REVIGRÉS
Type - Pset_ProductRequirements - Category: Walls
Type - Pset_QuantityTakeOff - Reference: 312GD3V721
Type - Pset_ReinforcementBarPitchOfWall - Description: Concrete effect in wall and floor porcelain tile.; Reference: 312GD3V721
Type - Pset_WallCommon - IsExternal: no; Reference: 312GD3V721
Type - IFC.REVIGRÉS-Dados do fabricante-Wall Covering - FabricanteURL: https://www.revigres.pt/; ReferenciaModelo: Rule; NumeroGlobalDeItemComercial: 312GD3V721; Acabamento: SILK; Material: Grés porcelânico; IdentificadorDoOperadorEconomico: 501840856; UrlFabricanteArtigo: https://www.revigres.pt/colecoes/rule; PaisOrigem: Portugal
Type - IFC.REVIGRÉS-Dados de desempenho-Wall Covering - Rectilinearidade: ± 0.2% máx.± 0.8 mm; Ortogonalidade: ± 0.2% máx.± 1.5 mm; PlanaridadeDaSuperficie: ± 0.3% máx. ± 1.8 mm; QualidadeDaSuperficie: Cumpre; AbsorcaoDeAgua: < 0.05%; ModuloDeRuptura: > 45 N/mm²; ResistenciaAFlexao: >3500 N; ResistenciaAAbrasaoProfunda: < 120 mm³; DilatacaoTermicaLinear: ≤ 8,0x10-6 °C-1; ResistenciaAoChoqueTermico: Resiste; DurabilidadeResistenciaAoGeloDegelo: Resiste; ResistenciaAoEscorregamentoDIN51130: R9; ResistenciaAoEscorregamentoDIN51097: A; ResistenciaAoEscorregamentoENV51097: A; ResistenciaAoEscorregamentoENV12633: Class 1; ResistenciaAoEscorregamentoANSIA1371: ≥0,42; ResistenciaAoDeslizamentoENV12633: Class 1; ResistenciaAsManchas: Class 5; ResistenciaABaixasConcentracoesDeAcidosEAlcalis: Classe LA; ResistenciaAAltasConcentracoesDeAcidosEAlcalis: Classe HA; LibertacaoDeCadmio: 0; LibertacaoDeChumbo: 0
Type - IFC.REVIGRÉS-Dados de especificação-Wall Covering - VariacaoTonalidade: 3; NivelDeTrafego: 5; EPavimento: Sim; ERevestimento: Sim; EExterno: Sim
Type - IFC.REVIGRÉS-Dados geométricos-Wall Covering - AlturaNominal: 10.5 mm; ComprimentoNominal: 59.2 mm; LarguraNominal: 118.6 mm
Type - IFC.REVIGRÉS-Dados de sustentabilidade-Wall Covering - PotencialPrivacaoDeAguaConsumoDeAguaPonderado: 4.5; EnergiaTermicaExportada: 0; ItemENovo: Sim; ItemEParcialmenteReciclado: 0.23; ItemEReciclado: Sim; VidaÚtilEsperada: 50; SubstanciasPerigosas: Não; PotencialDeEsgotamentoAbioticoDosRecursosFosseis: 203; PotencialDeEsgotamentoAbioticoDosRecursosNaoFosseisMineraisEMetais: 0.000701; PotencialDeAquecimentoGlobalBiogenico: -0.48; CombustiveisFosseisComPotencialDeAquecimentoGlobal: 13.9; PotencialDeAquecimentoGlobalUsoDoSoloEMudancaDeUsoDoSolo: 0.0246; PotencialDeEutrofizacaoFraccaoDeNutrientesQueAtingemOCompartimentoFinalDeAguaDoce: 0.000189; PotencialDeEutrofizacaoFraccaoDeNutrientesQueAtingemOCompartimentoFinalMarinho: 0.0122; EnergiaRecuperada: 0.00739; ConsumoDeAguaDoce: 0.113; UtilizacaoLiquidaDeAguaDoce: 0.113; ResiduosPerigososEliminados: 0.00221; ResiduosNaoPerigososEliminados: 1.83; MassaTotalDeResiduosRadioactivosEliminados: 0.000394; EnergiaElectricaExportada: 1.55; MateriaisParaRecuperacaoDeEnergia: 0.00739; MateriaisParaReciclagem: 0.0253; UnidadeEPD: 1 m²
Type - IFC.REVIGRÉS-Dados gerais-Wall Covering - Nome: REVIGRÉS-RULE-BASE-59.2X118.6-SILK-SMOG; TipoProduto: Prensado a seco: grupo BIa UGL | Grés porcelânico técnico; NumeroDeRegistoDAP: EPD-REV-20240006-CCC1-EN; ReferenciaDAP: -; UrlDOP: -
Pset_WallCommon - ExtendToStructure: no; LoadBearing: no
IFC.REVIGRÉS-Dados do fabricante-Wall Covering - Type: Basic Wall: REVIGRÉS-RULE-BASE-59,2x118,6-SILK-SMOG
IFC.REVIGRÉS-Dados de desempenho-Wall Covering - Type: Basic Wall: REVIGRÉS-RULE-BASE-59,2x118,6-SILK-SMOG
IFC.REVIGRÉS-Dados de especificação-Wall Covering - Type: Basic Wall: REVIGRÉS-RULE-BASE-59,2x118,6-SILK-SMOG
IFC.REVIGRÉS-Dados geométricos-Wall Covering - Type: Basic Wall: REVIGRÉS-RULE-BASE-59,2x118,6-SILK-SMOG
IFC.REVIGRÉS-Dados de sustentabilidade-Wall Covering - Type: Basic Wall: REVIGRÉS-RULE-BASE-59,2x118,6-SILK-SMOG

# IfcWallStandardCase: Basic Wall:REVIGRÉS-RULE-BASE-59,2x118,6-SOFT GRIP-ALLOY, Basic Wall:REVIGRÉS-RULE-BASE-59,2x118,6-SOFT GRIP-ALLOY:11877
In: Level 1
Type - PredefinedType: STANDARD; Material: REVIGRÉS-RULE-BASE-59.2x118.6-SOFT GRIP-ALLOY 10.5 mm
Type - Pset_ElementShading - Roughness: 304.8 mm
Type - Pset_ManufacturerTypeInformation - Manufacturer: REVIGRÉS
Type - Pset_ProductRequirements - Category: Walls
Type - Pset_QuantityTakeOff - Reference: 312FD3V711
Type - Pset_ReinforcementBarPitchOfWall - Description: Concrete effect in wall and floor porcelain tile.; Reference: 312FD3V711
Type - Pset_WallCommon - IsExternal: no; Reference: 312FD3V711
Type - IFC.REVIGRÉS-Dados do fabricante-Wall Covering - FabricanteURL: https://www.revigres.pt/; ReferenciaModelo: Rule; NumeroGlobalDeItemComercial: 312FD3V711; Acabamento: SOFT GRIP; Material: Grés porcelânico; IdentificadorDoOperadorEconomico: 501840856; UrlFabricanteArtigo: https://www.revigres.pt/colecoes/rule; PaisOrigem: Portugal
Type - IFC.REVIGRÉS-Dados de desempenho-Wall Covering - Rectilinearidade: ± 0.2% máx.± 0.8 mm; Ortogonalidade: ± 0.2% máx.± 1.5 mm; PlanaridadeDaSuperficie: ± 0.3% máx. ± 1.8 mm; QualidadeDaSuperficie: Cumpre; AbsorcaoDeAgua: < 0.05%; ModuloDeRuptura: > 45 N/mm²; ResistenciaAFlexao: >3500 N; ResistenciaAAbrasaoProfunda: < 120 mm³; DilatacaoTermicaLinear: ≤ 8,0x10-6 °C-1; ResistenciaAoChoqueTermico: Resiste; DurabilidadeResistenciaAoGeloDegelo: Resiste; ResistenciaAoEscorregamentoDIN51130: R11; ResistenciaAoEscorregamentoDIN51097: B; ResistenciaAoEscorregamentoENV51097: B; ResistenciaAoEscorregamentoENV12633: Class 2; ResistenciaAoEscorregamentoBS7976: >36; ResistenciaAoEscorregamentoANSIA1371: ≥0,42; ResistenciaAoDeslizamentoENV12633: Class 2; ResistenciaAoDeslizamentoBS7976: >36; ResistenciaAsManchas: Class 5; ResistenciaABaixasConcentracoesDeAcidosEAlcalis: Classe LA; ResistenciaAAltasConcentracoesDeAcidosEAlcalis: Classe HA; LibertacaoDeCadmio: 0; LibertacaoDeChumbo: 0
Type - IFC.REVIGRÉS-Dados de especificação-Wall Covering - VariacaoTonalidade: 3; NivelDeTrafego: 5; EPavimento: Sim; ERevestimento: Sim; EExterno: Sim
Type - IFC.REVIGRÉS-Dados geométricos-Wall Covering - AlturaNominal: 10.5 mm; ComprimentoNominal: 59.2 mm; LarguraNominal: 118.6 mm
Type - IFC.REVIGRÉS-Dados de sustentabilidade-Wall Covering - ItemEParcialmenteReciclado: 0; PotencialPrivacaoDeAguaConsumoDeAguaPonderado: 4.5; EnergiaTermicaExportada: 0; ItemENovo: Sim; ItemEReciclado: Não; VidaÚtilEsperada: 50; SubstanciasPerigosas: Não; PotencialDeEsgotamentoAbioticoDosRecursosFosseis: 203; PotencialDeEsgotamentoAbioticoDosRecursosNaoFosseisMineraisEMetais: 0.000701; PotencialDeAquecimentoGlobalBiogenico: -0.48; CombustiveisFosseisComPotencialDeAquecimentoGlobal: 13.9; PotencialDeAquecimentoGlobalUsoDoSoloEMudancaDeUsoDoSolo: 0.0246; PotencialDeEutrofizacaoFraccaoDeNutrientesQueAtingemOCompartimentoFinalDeAguaDoce: 0.000189; PotencialDeEutrofizacaoFraccaoDeNutrientesQueAtingemOCompartimentoFinalMarinho: 0.0122; EnergiaRecuperada: 0.00739; ConsumoDeAguaDoce: 0.113; UtilizacaoLiquidaDeAguaDoce: 0.113; ResiduosPerigososEliminados: 0.00221; ResiduosNaoPerigososEliminados: 1.83; MassaTotalDeResiduosRadioactivosEliminados: 0.000394; EnergiaElectricaExportada: 1.55; MateriaisParaRecuperacaoDeEnergia: 0.00739; MateriaisParaReciclagem: 0.0253; UnidadeEPD: 1 m²
Type - IFC.REVIGRÉS-Dados gerais-Wall Covering - Nome: REVIGRÉS-RULE-BASE-59.2X118.6-SOFT GRIP-ALLOY; TipoProduto: Prensado a seco: grupo BIa UGL | Grés porcelânico técnico; NumeroDeRegistoDAP: EPD-REV-20240006-CCC1-EN; ReferenciaDAP: -; UrlDOP: -
Pset_WallCommon - ExtendToStructure: no; LoadBearing: no
IFC.REVIGRÉS-Dados do fabricante-Wall Covering - Type: Basic Wall: REVIGRÉS-RULE-BASE-59,2x118,6-SOFT GRIP-ALLOY
IFC.REVIGRÉS-Dados de desempenho-Wall Covering - Type: Basic Wall: REVIGRÉS-RULE-BASE-59,2x118,6-SOFT GRIP-ALLOY
IFC.REVIGRÉS-Dados de especificação-Wall Covering - Type: Basic Wall: REVIGRÉS-RULE-BASE-59,2x118,6-SOFT GRIP-ALLOY
IFC.REVIGRÉS-Dados geométricos-Wall Covering - Type: Basic Wall: REVIGRÉS-RULE-BASE-59,2x118,6-SOFT GRIP-ALLOY
IFC.REVIGRÉS-Dados de sustentabilidade-Wall Covering - Type: Basic Wall: REVIGRÉS-RULE-BASE-59,2x118,6-SOFT GRIP-ALLOY

# IfcWallStandardCase: Basic Wall:REVIGRÉS-RULE-BASE-59,2x118,6-SOFT GRIP-SMOG, Basic Wall:REVIGRÉS-RULE-BASE-59,2x118,6-SOFT GRIP-SMOG:12179
In: Level 1
Type - PredefinedType: STANDARD; Material: REVIGRÉS-RULE-BASE-59.2x118.6-SOFT GRIP-SMOG 10.5 mm
Type - Pset_ElementShading - Roughness: 304.8 mm
Type - Pset_ManufacturerTypeInformation - Manufacturer: REVIGRÉS
Type - Pset_ProductRequirements - Category: Walls
Type - Pset_QuantityTakeOff - Reference: 312FD3V721
Type - Pset_ReinforcementBarPitchOfWall - Description: Concrete effect in wall and floor porcelain tile.; Reference: 312FD3V721
Type - Pset_WallCommon - IsExternal: no; Reference: 312FD3V721
Type - IFC.REVIGRÉS-Dados do fabricante-Wall Covering - FabricanteURL: https://www.revigres.pt/; ReferenciaModelo: Rule; NumeroGlobalDeItemComercial: 312FD3V721; Acabamento: SOFT GRIP; Material: Grés porcelânico; IdentificadorDoOperadorEconomico: 501840856; UrlFabricanteArtigo: https://www.revigres.pt/colecoes/rule; PaisOrigem: Portugal
Type - IFC.REVIGRÉS-Dados de desempenho-Wall Covering - Rectilinearidade: ± 0.2% máx.± 0.8 mm; Ortogonalidade: ± 0.2% máx.± 1.5 mm; PlanaridadeDaSuperficie: ± 0.3% máx. ± 1.8 mm; QualidadeDaSuperficie: Cumpre; AbsorcaoDeAgua: < 0.05%; ModuloDeRuptura: > 45 N/mm²; ResistenciaAFlexao: >3500 N; ResistenciaAAbrasaoProfunda: < 120 mm³; DilatacaoTermicaLinear: ≤ 8,0x10-6 °C-1; ResistenciaAoChoqueTermico: Resiste; DurabilidadeResistenciaAoGeloDegelo: Resiste; ResistenciaAoEscorregamentoDIN51130: R11; ResistenciaAoEscorregamentoDIN51097: B; ResistenciaAoEscorregamentoENV51097: B; ResistenciaAoEscorregamentoENV12633: Class 2; ResistenciaAoEscorregamentoBS7976: >36; ResistenciaAoEscorregamentoANSIA1371: ≥0,42; ResistenciaAoDeslizamentoENV12633: Class 2; ResistenciaAoDeslizamentoBS7976: >36; ResistenciaAsManchas: Class 5; ResistenciaABaixasConcentracoesDeAcidosEAlcalis: Classe LA; ResistenciaAAltasConcentracoesDeAcidosEAlcalis: Classe HA; LibertacaoDeCadmio: 0; LibertacaoDeChumbo: 0
Type - IFC.REVIGRÉS-Dados de especificação-Wall Covering - VariacaoTonalidade: 3; NivelDeTrafego: 5; EPavimento: Sim; ERevestimento: Sim; EExterno: Sim
Type - IFC.REVIGRÉS-Dados geométricos-Wall Covering - AlturaNominal: 10.5 mm; ComprimentoNominal: 59.2 mm; LarguraNominal: 118.6 mm
Type - IFC.REVIGRÉS-Dados de sustentabilidade-Wall Covering - PotencialPrivacaoDeAguaConsumoDeAguaPonderado: 4.5; EnergiaTermicaExportada: 0; ItemENovo: Sim; ItemEParcialmenteReciclado: 0.23; ItemEReciclado: Sim; VidaÚtilEsperada: 50; SubstanciasPerigosas: Não; PotencialDeEsgotamentoAbioticoDosRecursosFosseis: 203; PotencialDeEsgotamentoAbioticoDosRecursosNaoFosseisMineraisEMetais: 0.000701; PotencialDeAquecimentoGlobalBiogenico: -0.48; CombustiveisFosseisComPotencialDeAquecimentoGlobal: 13.9; PotencialDeAquecimentoGlobalUsoDoSoloEMudancaDeUsoDoSolo: 0.0246; PotencialDeEutrofizacaoFraccaoDeNutrientesQueAtingemOCompartimentoFinalDeAguaDoce: 0.000189; PotencialDeEutrofizacaoFraccaoDeNutrientesQueAtingemOCompartimentoFinalMarinho: 0.0122; EnergiaRecuperada: 0.00739; ConsumoDeAguaDoce: 0.113; UtilizacaoLiquidaDeAguaDoce: 0.113; ResiduosPerigososEliminados: 0.00221; ResiduosNaoPerigososEliminados: 1.83; MassaTotalDeResiduosRadioactivosEliminados: 0.000394; EnergiaElectricaExportada: 1.55; MateriaisParaRecuperacaoDeEnergia: 0.00739; MateriaisParaReciclagem: 0.0253; UnidadeEPD: 1 m²
Type - IFC.REVIGRÉS-Dados gerais-Wall Covering - Nome: REVIGRÉS-RULE-BASE-59.2X118.6-SOFT GRIP-SMOG; TipoProduto: Prensado a seco: grupo BIa UGL | Grés porcelânico técnico; NumeroDeRegistoDAP: EPD-REV-20240006-CCC1-EN; ReferenciaDAP: -; UrlDOP: -
Pset_WallCommon - ExtendToStructure: no; LoadBearing: no
IFC.REVIGRÉS-Dados do fabricante-Wall Covering - Type: Basic Wall: REVIGRÉS-RULE-BASE-59,2x118,6-SOFT GRIP-SMOG
IFC.REVIGRÉS-Dados de desempenho-Wall Covering - Type: Basic Wall: REVIGRÉS-RULE-BASE-59,2x118,6-SOFT GRIP-SMOG
IFC.REVIGRÉS-Dados de especificação-Wall Covering - Type: Basic Wall: REVIGRÉS-RULE-BASE-59,2x118,6-SOFT GRIP-SMOG
IFC.REVIGRÉS-Dados geométricos-Wall Covering - Type: Basic Wall: REVIGRÉS-RULE-BASE-59,2x118,6-SOFT GRIP-SMOG
IFC.REVIGRÉS-Dados de sustentabilidade-Wall Covering - Type: Basic Wall: REVIGRÉS-RULE-BASE-59,2x118,6-SOFT GRIP-SMOG

# IfcWallStandardCase: Basic Wall:REVIGRÉS-RULE-BASE-59,2x178-SILK-ALLOY, Basic Wall:REVIGRÉS-RULE-BASE-59,2x178-SILK-ALLOY:12000
In: Level 1
Type - PredefinedType: STANDARD; Material: REVIGRÉS-RULE-BASE-59.2x178-SILK-ALLOY 11.2 mm
Type - Pset_ElementShading - Roughness: 304.8 mm
Type - Pset_ManufacturerTypeInformation - Manufacturer: REVIGRÉS
Type - Pset_ProductRequirements - Category: Walls
Type - Pset_QuantityTakeOff - Reference: 312GS5V711
Type - Pset_ReinforcementBarPitchOfWall - Description: Concrete effect in wall and floor porcelain tile.; Reference: 312GS5V711
Type - Pset_WallCommon - IsExternal: no; Reference: 312GS5V711
Type - IFC.REVIGRÉS-Dados do fabricante-Wall Covering - FabricanteURL: https://www.revigres.pt/; ReferenciaModelo: Rule; NumeroGlobalDeItemComercial: 312GS5V711; Acabamento: SILK; Material: Grés porcelânico; IdentificadorDoOperadorEconomico: 501840856; UrlFabricanteArtigo: https://www.revigres.pt/colecoes/rule; PaisOrigem: Portugal
Type - IFC.REVIGRÉS-Dados de desempenho-Wall Covering - Rectilinearidade: ± 0.2% máx.± 0.8 mm; Ortogonalidade: ± 0.2% máx.± 1.5 mm; PlanaridadeDaSuperficie: ± 0.3% máx. ± 1.8 mm; QualidadeDaSuperficie: Cumpre; AbsorcaoDeAgua: < 0.05%; ModuloDeRuptura: > 45 N/mm²; ResistenciaAFlexao: >3500 N; ResistenciaAAbrasaoProfunda: < 120 mm³; DilatacaoTermicaLinear: ≤ 8,0x10-6 °C-1; ResistenciaAoChoqueTermico: Resiste; DurabilidadeResistenciaAoGeloDegelo: Resiste; ResistenciaAoEscorregamentoDIN51130: R9; ResistenciaAoEscorregamentoDIN51097: A; ResistenciaAoEscorregamentoENV51097: A; ResistenciaAoEscorregamentoENV12633: Class 1; ResistenciaAoEscorregamentoANSIA1371: ≥0,42; ResistenciaAoDeslizamentoENV12633: Class 1; ResistenciaAsManchas: Class 5; ResistenciaABaixasConcentracoesDeAcidosEAlcalis: Classe LA; ResistenciaAAltasConcentracoesDeAcidosEAlcalis: Classe HA; LibertacaoDeCadmio: 0; LibertacaoDeChumbo: 0
Type - IFC.REVIGRÉS-Dados de especificação-Wall Covering - VariacaoTonalidade: 3; NivelDeTrafego: 5; EPavimento: Sim; ERevestimento: Sim; EExterno: Sim
Type - IFC.REVIGRÉS-Dados geométricos-Wall Covering - AlturaNominal: 11.2 mm; ComprimentoNominal: 59.2 mm; LarguraNominal: 178 mm
Type - IFC.REVIGRÉS-Dados de sustentabilidade-Wall Covering - ItemEParcialmenteReciclado: 0; PotencialPrivacaoDeAguaConsumoDeAguaPonderado: 4.5; EnergiaTermicaExportada: 0; ItemENovo: Sim; ItemEReciclado: Não; VidaÚtilEsperada: 50; SubstanciasPerigosas: Não; PotencialDeEsgotamentoAbioticoDosRecursosFosseis: 203; PotencialDeEsgotamentoAbioticoDosRecursosNaoFosseisMineraisEMetais: 0.000701; PotencialDeAquecimentoGlobalBiogenico: -0.48; CombustiveisFosseisComPotencialDeAquecimentoGlobal: 13.9; PotencialDeAquecimentoGlobalUsoDoSoloEMudancaDeUsoDoSolo: 0.0246; PotencialDeEutrofizacaoFraccaoDeNutrientesQueAtingemOCompartimentoFinalDeAguaDoce: 0.000189; PotencialDeEutrofizacaoFraccaoDeNutrientesQueAtingemOCompartimentoFinalMarinho: 0.0122; EnergiaRecuperada: 0.00739; ConsumoDeAguaDoce: 0.113; UtilizacaoLiquidaDeAguaDoce: 0.113; ResiduosPerigososEliminados: 0.00221; ResiduosNaoPerigososEliminados: 1.83; MassaTotalDeResiduosRadioactivosEliminados: 0.000394; EnergiaElectricaExportada: 1.55; MateriaisParaRecuperacaoDeEnergia: 0.00739; MateriaisParaReciclagem: 0.0253; UnidadeEPD: 1 m²
Type - IFC.REVIGRÉS-Dados gerais-Wall Covering - Nome: REVIGRÉS-RULE-BASE-59.2X178-SILK-ALLOY; TipoProduto: Prensado a seco: grupo BIa UGL | Grés porcelânico técnico; NumeroDeRegistoDAP: EPD-REV-20240006-CCC1-EN; ReferenciaDAP: -; UrlDOP: -
Pset_WallCommon - ExtendToStructure: no; LoadBearing: no
IFC.REVIGRÉS-Dados do fabricante-Wall Covering - Type: Basic Wall: REVIGRÉS-RULE-BASE-59,2x178-SILK-ALLOY
IFC.REVIGRÉS-Dados de desempenho-Wall Covering - Type: Basic Wall: REVIGRÉS-RULE-BASE-59,2x178-SILK-ALLOY
IFC.REVIGRÉS-Dados de especificação-Wall Covering - Type: Basic Wall: REVIGRÉS-RULE-BASE-59,2x178-SILK-ALLOY
IFC.REVIGRÉS-Dados geométricos-Wall Covering - Type: Basic Wall: REVIGRÉS-RULE-BASE-59,2x178-SILK-ALLOY
IFC.REVIGRÉS-Dados de sustentabilidade-Wall Covering - Type: Basic Wall: REVIGRÉS-RULE-BASE-59,2x178-SILK-ALLOY

# IfcWallStandardCase: Basic Wall:REVIGRÉS-RULE-BASE-59,2x178-SILK-SMOG, Basic Wall:REVIGRÉS-RULE-BASE-59,2x178-SILK-SMOG:12189
In: Level 1
Type - PredefinedType: STANDARD; Material: REVIGRÉS-RULE-BASE-59.2x178-SILK-SMOG 11.2 mm
Type - Pset_ElementShading - Roughness: 304.8 mm
Type - Pset_ManufacturerTypeInformation - Manufacturer: REVIGRÉS
Type - Pset_ProductRequirements - Category: Walls
Type - Pset_QuantityTakeOff - Reference: 312GS5V721
Type - Pset_ReinforcementBarPitchOfWall - Description: Concrete effect in wall and floor porcelain tile.; Reference: 312GS5V721
Type - Pset_WallCommon - IsExternal: no; Reference: 312GS5V721
Type - IFC.REVIGRÉS-Dados do fabricante-Wall Covering - FabricanteURL: https://www.revigres.pt/; ReferenciaModelo: Rule; NumeroGlobalDeItemComercial: 312GS5V721; Acabamento: SILK; Material: Grés porcelânico; IdentificadorDoOperadorEconomico: 501840856; UrlFabricanteArtigo: https://www.revigres.pt/colecoes/rule; PaisOrigem: Portugal
Type - IFC.REVIGRÉS-Dados de desempenho-Wall Covering - Rectilinearidade: ± 0.2% máx.± 0.8 mm; Ortogonalidade: ± 0.2% máx.± 1.5 mm; PlanaridadeDaSuperficie: ± 0.3% máx. ± 1.8 mm; QualidadeDaSuperficie: Cumpre; AbsorcaoDeAgua: < 0.05%; ModuloDeRuptura: > 45 N/mm²; ResistenciaAFlexao: >3500 N; ResistenciaAAbrasaoProfunda: < 120 mm³; DilatacaoTermicaLinear: ≤ 8,0x10-6 °C-1; ResistenciaAoChoqueTermico: Resiste; DurabilidadeResistenciaAoGeloDegelo: Resiste; ResistenciaAoEscorregamentoDIN51130: R9; ResistenciaAoEscorregamentoDIN51097: A; ResistenciaAoEscorregamentoENV51097: A; ResistenciaAoEscorregamentoENV12633: Class 1; ResistenciaAoEscorregamentoANSIA1371: ≥0,42; ResistenciaAoDeslizamentoENV12633: Class 1; ResistenciaAsManchas: Class 5; ResistenciaABaixasConcentracoesDeAcidosEAlcalis: Classe LA; ResistenciaAAltasConcentracoesDeAcidosEAlcalis: Classe HA; LibertacaoDeCadmio: 0; LibertacaoDeChumbo: 0
Type - IFC.REVIGRÉS-Dados de especificação-Wall Covering - VariacaoTonalidade: 3; NivelDeTrafego: 5; EPavimento: Sim; ERevestimento: Sim; EExterno: Sim
Type - IFC.REVIGRÉS-Dados geométricos-Wall Covering - AlturaNominal: 11.2 mm; ComprimentoNominal: 59.2 mm; LarguraNominal: 178 mm
Type - IFC.REVIGRÉS-Dados de sustentabilidade-Wall Covering - PotencialPrivacaoDeAguaConsumoDeAguaPonderado: 4.5; EnergiaTermicaExportada: 0; ItemENovo: Sim; ItemEParcialmenteReciclado: 0.23; ItemEReciclado: Sim; VidaÚtilEsperada: 50; SubstanciasPerigosas: Não; PotencialDeEsgotamentoAbioticoDosRecursosFosseis: 203; PotencialDeEsgotamentoAbioticoDosRecursosNaoFosseisMineraisEMetais: 0.000701; PotencialDeAquecimentoGlobalBiogenico: -0.48; CombustiveisFosseisComPotencialDeAquecimentoGlobal: 13.9; PotencialDeAquecimentoGlobalUsoDoSoloEMudancaDeUsoDoSolo: 0.0246; PotencialDeEutrofizacaoFraccaoDeNutrientesQueAtingemOCompartimentoFinalDeAguaDoce: 0.000189; PotencialDeEutrofizacaoFraccaoDeNutrientesQueAtingemOCompartimentoFinalMarinho: 0.0122; EnergiaRecuperada: 0.00739; ConsumoDeAguaDoce: 0.113; UtilizacaoLiquidaDeAguaDoce: 0.113; ResiduosPerigososEliminados: 0.00221; ResiduosNaoPerigososEliminados: 1.83; MassaTotalDeResiduosRadioactivosEliminados: 0.000394; EnergiaElectricaExportada: 1.55; MateriaisParaRecuperacaoDeEnergia: 0.00739; MateriaisParaReciclagem: 0.0253; UnidadeEPD: 1 m²
Type - IFC.REVIGRÉS-Dados gerais-Wall Covering - Nome: REVIGRÉS-RULE-BASE-59.2X178-SILK-SMOG; TipoProduto: Prensado a seco: grupo BIa UGL | Grés porcelânico técnico; NumeroDeRegistoDAP: EPD-REV-20240006-CCC1-EN; ReferenciaDAP: -; UrlDOP: -
Pset_WallCommon - ExtendToStructure: no; LoadBearing: no
IFC.REVIGRÉS-Dados do fabricante-Wall Covering - Type: Basic Wall: REVIGRÉS-RULE-BASE-59,2x178-SILK-SMOG
IFC.REVIGRÉS-Dados de desempenho-Wall Covering - Type: Basic Wall: REVIGRÉS-RULE-BASE-59,2x178-SILK-SMOG
IFC.REVIGRÉS-Dados de especificação-Wall Covering - Type: Basic Wall: REVIGRÉS-RULE-BASE-59,2x178-SILK-SMOG
IFC.REVIGRÉS-Dados geométricos-Wall Covering - Type: Basic Wall: REVIGRÉS-RULE-BASE-59,2x178-SILK-SMOG
IFC.REVIGRÉS-Dados de sustentabilidade-Wall Covering - Type: Basic Wall: REVIGRÉS-RULE-BASE-59,2x178-SILK-SMOG

# IfcWallStandardCase: Basic Wall:REVIGRÉS-RULE-BASE-59,2x178-SOFT GRIP-ALLOY, Basic Wall:REVIGRÉS-RULE-BASE-59,2x178-SOFT GRIP-ALLOY:12008
In: Level 1
Type - PredefinedType: STANDARD; Material: REVIGRÉS-RULE-BASE-59.2x178-SOFT GRIP-ALLOY 11.2 mm
Type - Pset_ElementShading - Roughness: 304.8 mm
Type - Pset_ManufacturerTypeInformation - Manufacturer: REVIGRÉS
Type - Pset_ProductRequirements - Category: Walls
Type - Pset_QuantityTakeOff - Reference: 312FS5V711
Type - Pset_ReinforcementBarPitchOfWall - Description: Concrete effect in wall and floor porcelain tile.; Reference: 312FS5V711
Type - Pset_WallCommon - IsExternal: no; Reference: 312FS5V711
Type - IFC.REVIGRÉS-Dados do fabricante-Wall Covering - FabricanteURL: https://www.revigres.pt/; ReferenciaModelo: Rule; NumeroGlobalDeItemComercial: 312FS5V711; Acabamento: SOFT GRIP; Material: Grés porcelânico; IdentificadorDoOperadorEconomico: 501840856; UrlFabricanteArtigo: https://www.revigres.pt/colecoes/rule; PaisOrigem: Portugal
Type - IFC.REVIGRÉS-Dados de desempenho-Wall Covering - Rectilinearidade: ± 0.2% máx.± 0.8 mm; Ortogonalidade: ± 0.2% máx.± 1.5 mm; PlanaridadeDaSuperficie: ± 0.3% máx. ± 1.8 mm; QualidadeDaSuperficie: Cumpre; AbsorcaoDeAgua: < 0.05%; ModuloDeRuptura: > 45 N/mm²; ResistenciaAFlexao: >3500 N; ResistenciaAAbrasaoProfunda: < 120 mm³; DilatacaoTermicaLinear: ≤ 8,0x10-6 °C-1; ResistenciaAoChoqueTermico: Resiste; DurabilidadeResistenciaAoGeloDegelo: Resiste; ResistenciaAoEscorregamentoDIN51130: R11; ResistenciaAoEscorregamentoDIN51097: B; ResistenciaAoEscorregamentoENV51097: B; ResistenciaAoEscorregamentoENV12633: Class 2; ResistenciaAoEscorregamentoBS7976: >36; ResistenciaAoEscorregamentoANSIA1371: ≥0,42; ResistenciaAoDeslizamentoENV12633: Class 2; ResistenciaAoDeslizamentoBS7976: >36; ResistenciaAsManchas: Class 5; ResistenciaABaixasConcentracoesDeAcidosEAlcalis: Classe LA; ResistenciaAAltasConcentracoesDeAcidosEAlcalis: Classe HA; LibertacaoDeCadmio: 0; LibertacaoDeChumbo: 0
Type - IFC.REVIGRÉS-Dados de especificação-Wall Covering - VariacaoTonalidade: 3; NivelDeTrafego: 5; EPavimento: Sim; ERevestimento: Sim; EExterno: Sim
Type - IFC.REVIGRÉS-Dados geométricos-Wall Covering - AlturaNominal: 11.2 mm; ComprimentoNominal: 59.2 mm; LarguraNominal: 178 mm
Type - IFC.REVIGRÉS-Dados de sustentabilidade-Wall Covering - ItemEParcialmenteReciclado: 0; PotencialPrivacaoDeAguaConsumoDeAguaPonderado: 4.5; EnergiaTermicaExportada: 0; ItemENovo: Sim; ItemEReciclado: Não; VidaÚtilEsperada: 50; SubstanciasPerigosas: Não; PotencialDeEsgotamentoAbioticoDosRecursosFosseis: 203; PotencialDeEsgotamentoAbioticoDosRecursosNaoFosseisMineraisEMetais: 0.000701; PotencialDeAquecimentoGlobalBiogenico: -0.48; CombustiveisFosseisComPotencialDeAquecimentoGlobal: 13.9; PotencialDeAquecimentoGlobalUsoDoSoloEMudancaDeUsoDoSolo: 0.0246; PotencialDeEutrofizacaoFraccaoDeNutrientesQueAtingemOCompartimentoFinalDeAguaDoce: 0.000189; PotencialDeEutrofizacaoFraccaoDeNutrientesQueAtingemOCompartimentoFinalMarinho: 0.0122; EnergiaRecuperada: 0.00739; ConsumoDeAguaDoce: 0.113; UtilizacaoLiquidaDeAguaDoce: 0.113; ResiduosPerigososEliminados: 0.00221; ResiduosNaoPerigososEliminados: 1.83; MassaTotalDeResiduosRadioactivosEliminados: 0.000394; EnergiaElectricaExportada: 1.55; MateriaisParaRecuperacaoDeEnergia: 0.00739; MateriaisParaReciclagem: 0.0253; UnidadeEPD: 1 m²
Type - IFC.REVIGRÉS-Dados gerais-Wall Covering - Nome: REVIGRÉS-RULE-BASE-59.2X178-SOFT GRIP-ALLOY; TipoProduto: Prensado a seco: grupo BIa UGL | Grés porcelânico técnico; NumeroDeRegistoDAP: EPD-REV-20240006-CCC1-EN; ReferenciaDAP: -; UrlDOP: -
Pset_WallCommon - ExtendToStructure: no; LoadBearing: no
IFC.REVIGRÉS-Dados do fabricante-Wall Covering - Type: Basic Wall: REVIGRÉS-RULE-BASE-59,2x178-SOFT GRIP-ALLOY
IFC.REVIGRÉS-Dados de desempenho-Wall Covering - Type: Basic Wall: REVIGRÉS-RULE-BASE-59,2x178-SOFT GRIP-ALLOY
IFC.REVIGRÉS-Dados de especificação-Wall Covering - Type: Basic Wall: REVIGRÉS-RULE-BASE-59,2x178-SOFT GRIP-ALLOY
IFC.REVIGRÉS-Dados geométricos-Wall Covering - Type: Basic Wall: REVIGRÉS-RULE-BASE-59,2x178-SOFT GRIP-ALLOY
IFC.REVIGRÉS-Dados de sustentabilidade-Wall Covering - Type: Basic Wall: REVIGRÉS-RULE-BASE-59,2x178-SOFT GRIP-ALLOY

# IfcWallStandardCase: Basic Wall:REVIGRÉS-RULE-BASE-59,2x178-SOFT GRIP-SMOG, Basic Wall:REVIGRÉS-RULE-BASE-59,2x178-SOFT GRIP-SMOG:12197
In: Level 1
Type - PredefinedType: STANDARD; Material: REVIGRÉS-RULE-BASE-59.2x178-SOFT GRIP-SMOG 11.2 mm
Type - Pset_ElementShading - Roughness: 304.8 mm
Type - Pset_ManufacturerTypeInformation - Manufacturer: REVIGRÉS
Type - Pset_ProductRequirements - Category: Walls
Type - Pset_QuantityTakeOff - Reference: 312FS5V721
Type - Pset_ReinforcementBarPitchOfWall - Description: Concrete effect in wall and floor porcelain tile.; Reference: 312FS5V721
Type - Pset_WallCommon - IsExternal: no; Reference: 312FS5V721
Type - IFC.REVIGRÉS-Dados do fabricante-Wall Covering - FabricanteURL: https://www.revigres.pt/; ReferenciaModelo: Rule; NumeroGlobalDeItemComercial: 312FS5V721; Acabamento: SOFT GRIP; Material: Grés porcelânico; IdentificadorDoOperadorEconomico: 501840856; UrlFabricanteArtigo: https://www.revigres.pt/colecoes/rule; PaisOrigem: Portugal
Type - IFC.REVIGRÉS-Dados de desempenho-Wall Covering - Rectilinearidade: ± 0.2% máx.± 0.8 mm; Ortogonalidade: ± 0.2% máx.± 1.5 mm; PlanaridadeDaSuperficie: ± 0.3% máx. ± 1.8 mm; QualidadeDaSuperficie: Cumpre; AbsorcaoDeAgua: < 0.05%; ModuloDeRuptura: > 45 N/mm²; ResistenciaAFlexao: >3500 N; ResistenciaAAbrasaoProfunda: < 120 mm³; DilatacaoTermicaLinear: ≤ 8,0x10-6 °C-1; ResistenciaAoChoqueTermico: Resiste; DurabilidadeResistenciaAoGeloDegelo: Resiste; ResistenciaAoEscorregamentoDIN51130: R11; ResistenciaAoEscorregamentoDIN51097: B; ResistenciaAoEscorregamentoENV51097: B; ResistenciaAoEscorregamentoENV12633: Class 2; ResistenciaAoEscorregamentoBS7976: >36; ResistenciaAoEscorregamentoANSIA1371: ≥0,42; ResistenciaAoDeslizamentoENV12633: Class 2; ResistenciaAoDeslizamentoBS7976: >36; ResistenciaAsManchas: Class 5; ResistenciaABaixasConcentracoesDeAcidosEAlcalis: Classe LA; ResistenciaAAltasConcentracoesDeAcidosEAlcalis: Classe HA; LibertacaoDeCadmio: 0; LibertacaoDeChumbo: 0
Type - IFC.REVIGRÉS-Dados de especificação-Wall Covering - VariacaoTonalidade: 3; NivelDeTrafego: 5; EPavimento: Sim; ERevestimento: Sim; EExterno: Sim
Type - IFC.REVIGRÉS-Dados geométricos-Wall Covering - AlturaNominal: 11.2 mm; ComprimentoNominal: 59.2 mm; LarguraNominal: 178 mm
Type - IFC.REVIGRÉS-Dados de sustentabilidade-Wall Covering - PotencialPrivacaoDeAguaConsumoDeAguaPonderado: 4.5; EnergiaTermicaExportada: 0; ItemENovo: Sim; ItemEParcialmenteReciclado: 0.23; ItemEReciclado: Sim; VidaÚtilEsperada: 50; SubstanciasPerigosas: Não; PotencialDeEsgotamentoAbioticoDosRecursosFosseis: 203; PotencialDeEsgotamentoAbioticoDosRecursosNaoFosseisMineraisEMetais: 0.000701; PotencialDeAquecimentoGlobalBiogenico: -0.48; CombustiveisFosseisComPotencialDeAquecimentoGlobal: 13.9; PotencialDeAquecimentoGlobalUsoDoSoloEMudancaDeUsoDoSolo: 0.0246; PotencialDeEutrofizacaoFraccaoDeNutrientesQueAtingemOCompartimentoFinalDeAguaDoce: 0.000189; PotencialDeEutrofizacaoFraccaoDeNutrientesQueAtingemOCompartimentoFinalMarinho: 0.0122; EnergiaRecuperada: 0.00739; ConsumoDeAguaDoce: 0.113; UtilizacaoLiquidaDeAguaDoce: 0.113; ResiduosPerigososEliminados: 0.00221; ResiduosNaoPerigososEliminados: 1.83; MassaTotalDeResiduosRadioactivosEliminados: 0.000394; EnergiaElectricaExportada: 1.55; MateriaisParaRecuperacaoDeEnergia: 0.00739; MateriaisParaReciclagem: 0.0253; UnidadeEPD: 1 m²
Type - IFC.REVIGRÉS-Dados gerais-Wall Covering - Nome: REVIGRÉS-RULE-BASE-59.2X178-SOFT GRIP-SMOG; TipoProduto: Prensado a seco: grupo BIa UGL | Grés porcelânico técnico; NumeroDeRegistoDAP: EPD-REV-20240006-CCC1-EN; ReferenciaDAP: -; UrlDOP: -
Pset_WallCommon - ExtendToStructure: no; LoadBearing: no
IFC.REVIGRÉS-Dados do fabricante-Wall Covering - Type: Basic Wall: REVIGRÉS-RULE-BASE-59,2x178-SOFT GRIP-SMOG
IFC.REVIGRÉS-Dados de desempenho-Wall Covering - Type: Basic Wall: REVIGRÉS-RULE-BASE-59,2x178-SOFT GRIP-SMOG
IFC.REVIGRÉS-Dados de especificação-Wall Covering - Type: Basic Wall: REVIGRÉS-RULE-BASE-59,2x178-SOFT GRIP-SMOG
IFC.REVIGRÉS-Dados geométricos-Wall Covering - Type: Basic Wall: REVIGRÉS-RULE-BASE-59,2x178-SOFT GRIP-SMOG
IFC.REVIGRÉS-Dados de sustentabilidade-Wall Covering - Type: Basic Wall: REVIGRÉS-RULE-BASE-59,2x178-SOFT GRIP-SMOG
